VERSION 5.8 ;
BUSBITCHARS "[]" ;
DIVIDERCHAR "/" ;
UNITS
    DATABASE MICRONS 1000 ;
END UNITS

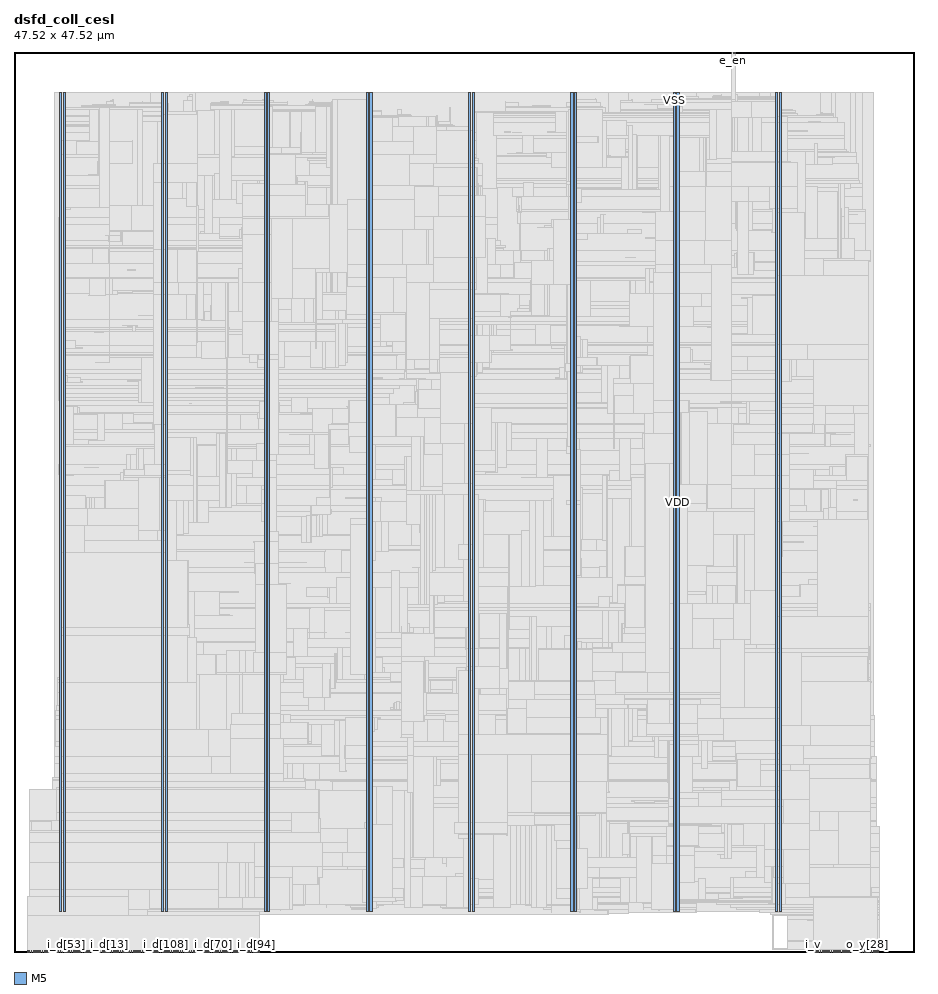
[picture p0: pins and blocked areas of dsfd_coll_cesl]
MACRO dsfd_coll_cesl
  FOREIGN dsfd_coll_cesl 0 0 ;
  CLASS BLOCK ;
  SIZE 47.52 BY 47.52 ;
  PIN ck
    DIRECTION INPUT ;
    USE SIGNAL ;
    PORT
      LAYER M5 ;
        RECT  37.872 47.436 37.896 47.52 ;
    END
  END ck
  PIN e_en
    DIRECTION INPUT ;
    USE SIGNAL ;
    PORT
      LAYER M5 ;
        RECT  37.968 47.436 37.992 47.52 ;
    END
  END e_en
  PIN i_d[0]
    DIRECTION INPUT ;
    USE SIGNAL ;
    PORT
      LAYER M5 ;
        RECT  3.792 0 3.816 0.084 ;
    END
  END i_d[0]
  PIN i_d[100]
    DIRECTION INPUT ;
    USE SIGNAL ;
    PORT
      LAYER M5 ;
        RECT  7.248 0 7.272 0.084 ;
    END
  END i_d[100]
  PIN i_d[101]
    DIRECTION INPUT ;
    USE SIGNAL ;
    PORT
      LAYER M5 ;
        RECT  7.344 0 7.368 0.084 ;
    END
  END i_d[101]
  PIN i_d[102]
    DIRECTION INPUT ;
    USE SIGNAL ;
    PORT
      LAYER M5 ;
        RECT  7.44 0 7.464 0.084 ;
    END
  END i_d[102]
  PIN i_d[103]
    DIRECTION INPUT ;
    USE SIGNAL ;
    PORT
      LAYER M5 ;
        RECT  7.536 0 7.56 0.084 ;
    END
  END i_d[103]
  PIN i_d[104]
    DIRECTION INPUT ;
    USE SIGNAL ;
    PORT
      LAYER M5 ;
        RECT  7.632 0 7.656 0.084 ;
    END
  END i_d[104]
  PIN i_d[105]
    DIRECTION INPUT ;
    USE SIGNAL ;
    PORT
      LAYER M5 ;
        RECT  7.728 0 7.752 0.084 ;
    END
  END i_d[105]
  PIN i_d[106]
    DIRECTION INPUT ;
    USE SIGNAL ;
    PORT
      LAYER M5 ;
        RECT  7.824 0 7.848 0.084 ;
    END
  END i_d[106]
  PIN i_d[107]
    DIRECTION INPUT ;
    USE SIGNAL ;
    PORT
      LAYER M5 ;
        RECT  7.92 0 7.944 0.084 ;
    END
  END i_d[107]
  PIN i_d[108]
    DIRECTION INPUT ;
    USE SIGNAL ;
    PORT
      LAYER M5 ;
        RECT  8.016 0 8.04 0.084 ;
    END
  END i_d[108]
  PIN i_d[109]
    DIRECTION INPUT ;
    USE SIGNAL ;
    PORT
      LAYER M5 ;
        RECT  8.112 0 8.136 0.084 ;
    END
  END i_d[109]
  PIN i_d[10]
    DIRECTION INPUT ;
    USE SIGNAL ;
    PORT
      LAYER M5 ;
        RECT  4.752 0 4.776 0.084 ;
    END
  END i_d[10]
  PIN i_d[110]
    DIRECTION INPUT ;
    USE SIGNAL ;
    PORT
      LAYER M5 ;
        RECT  8.208 0 8.232 0.084 ;
    END
  END i_d[110]
  PIN i_d[111]
    DIRECTION INPUT ;
    USE SIGNAL ;
    PORT
      LAYER M5 ;
        RECT  8.304 0 8.328 0.084 ;
    END
  END i_d[111]
  PIN i_d[112]
    DIRECTION INPUT ;
    USE SIGNAL ;
    PORT
      LAYER M5 ;
        RECT  8.4 0 8.424 0.084 ;
    END
  END i_d[112]
  PIN i_d[113]
    DIRECTION INPUT ;
    USE SIGNAL ;
    PORT
      LAYER M5 ;
        RECT  8.496 0 8.52 0.084 ;
    END
  END i_d[113]
  PIN i_d[114]
    DIRECTION INPUT ;
    USE SIGNAL ;
    PORT
      LAYER M5 ;
        RECT  8.592 0 8.616 0.084 ;
    END
  END i_d[114]
  PIN i_d[115]
    DIRECTION INPUT ;
    USE SIGNAL ;
    PORT
      LAYER M5 ;
        RECT  8.688 0 8.712 0.084 ;
    END
  END i_d[115]
  PIN i_d[116]
    DIRECTION INPUT ;
    USE SIGNAL ;
    PORT
      LAYER M5 ;
        RECT  8.784 0 8.808 0.084 ;
    END
  END i_d[116]
  PIN i_d[117]
    DIRECTION INPUT ;
    USE SIGNAL ;
    PORT
      LAYER M5 ;
        RECT  8.88 0 8.904 0.084 ;
    END
  END i_d[117]
  PIN i_d[118]
    DIRECTION INPUT ;
    USE SIGNAL ;
    PORT
      LAYER M5 ;
        RECT  8.976 0 9 0.084 ;
    END
  END i_d[118]
  PIN i_d[119]
    DIRECTION INPUT ;
    USE SIGNAL ;
    PORT
      LAYER M5 ;
        RECT  9.072 0 9.096 0.084 ;
    END
  END i_d[119]
  PIN i_d[11]
    DIRECTION INPUT ;
    USE SIGNAL ;
    PORT
      LAYER M5 ;
        RECT  4.848 0 4.872 0.084 ;
    END
  END i_d[11]
  PIN i_d[120]
    DIRECTION INPUT ;
    USE SIGNAL ;
    PORT
      LAYER M5 ;
        RECT  9.168 0 9.192 0.084 ;
    END
  END i_d[120]
  PIN i_d[121]
    DIRECTION INPUT ;
    USE SIGNAL ;
    PORT
      LAYER M5 ;
        RECT  9.264 0 9.288 0.084 ;
    END
  END i_d[121]
  PIN i_d[122]
    DIRECTION INPUT ;
    USE SIGNAL ;
    PORT
      LAYER M5 ;
        RECT  9.36 0 9.384 0.084 ;
    END
  END i_d[122]
  PIN i_d[123]
    DIRECTION INPUT ;
    USE SIGNAL ;
    PORT
      LAYER M5 ;
        RECT  9.456 0 9.48 0.084 ;
    END
  END i_d[123]
  PIN i_d[124]
    DIRECTION INPUT ;
    USE SIGNAL ;
    PORT
      LAYER M5 ;
        RECT  9.552 0 9.576 0.084 ;
    END
  END i_d[124]
  PIN i_d[125]
    DIRECTION INPUT ;
    USE SIGNAL ;
    PORT
      LAYER M5 ;
        RECT  9.648 0 9.672 0.084 ;
    END
  END i_d[125]
  PIN i_d[126]
    DIRECTION INPUT ;
    USE SIGNAL ;
    PORT
      LAYER M5 ;
        RECT  9.744 0 9.768 0.084 ;
    END
  END i_d[126]
  PIN i_d[127]
    DIRECTION INPUT ;
    USE SIGNAL ;
    PORT
      LAYER M5 ;
        RECT  9.84 0 9.864 0.084 ;
    END
  END i_d[127]
  PIN i_d[12]
    DIRECTION INPUT ;
    USE SIGNAL ;
    PORT
      LAYER M5 ;
        RECT  4.944 0 4.968 0.084 ;
    END
  END i_d[12]
  PIN i_d[13]
    DIRECTION INPUT ;
    USE SIGNAL ;
    PORT
      LAYER M5 ;
        RECT  5.04 0 5.064 0.084 ;
    END
  END i_d[13]
  PIN i_d[14]
    DIRECTION INPUT ;
    USE SIGNAL ;
    PORT
      LAYER M5 ;
        RECT  5.136 0 5.16 0.084 ;
    END
  END i_d[14]
  PIN i_d[15]
    DIRECTION INPUT ;
    USE SIGNAL ;
    PORT
      LAYER M5 ;
        RECT  5.232 0 5.256 0.084 ;
    END
  END i_d[15]
  PIN i_d[16]
    DIRECTION INPUT ;
    USE SIGNAL ;
    PORT
      LAYER M5 ;
        RECT  5.328 0 5.352 0.084 ;
    END
  END i_d[16]
  PIN i_d[17]
    DIRECTION INPUT ;
    USE SIGNAL ;
    PORT
      LAYER M5 ;
        RECT  5.424 0 5.448 0.084 ;
    END
  END i_d[17]
  PIN i_d[18]
    DIRECTION INPUT ;
    USE SIGNAL ;
    PORT
      LAYER M5 ;
        RECT  5.52 0 5.544 0.084 ;
    END
  END i_d[18]
  PIN i_d[19]
    DIRECTION INPUT ;
    USE SIGNAL ;
    PORT
      LAYER M5 ;
        RECT  5.616 0 5.64 0.084 ;
    END
  END i_d[19]
  PIN i_d[1]
    DIRECTION INPUT ;
    USE SIGNAL ;
    PORT
      LAYER M5 ;
        RECT  3.888 0 3.912 0.084 ;
    END
  END i_d[1]
  PIN i_d[20]
    DIRECTION INPUT ;
    USE SIGNAL ;
    PORT
      LAYER M5 ;
        RECT  5.712 0 5.736 0.084 ;
    END
  END i_d[20]
  PIN i_d[21]
    DIRECTION INPUT ;
    USE SIGNAL ;
    PORT
      LAYER M5 ;
        RECT  5.808 0 5.832 0.084 ;
    END
  END i_d[21]
  PIN i_d[22]
    DIRECTION INPUT ;
    USE SIGNAL ;
    PORT
      LAYER M5 ;
        RECT  5.904 0 5.928 0.084 ;
    END
  END i_d[22]
  PIN i_d[23]
    DIRECTION INPUT ;
    USE SIGNAL ;
    PORT
      LAYER M5 ;
        RECT  6 0 6.024 0.084 ;
    END
  END i_d[23]
  PIN i_d[24]
    DIRECTION INPUT ;
    USE SIGNAL ;
    PORT
      LAYER M5 ;
        RECT  6.096 0 6.12 0.084 ;
    END
  END i_d[24]
  PIN i_d[25]
    DIRECTION INPUT ;
    USE SIGNAL ;
    PORT
      LAYER M5 ;
        RECT  6.192 0 6.216 0.084 ;
    END
  END i_d[25]
  PIN i_d[26]
    DIRECTION INPUT ;
    USE SIGNAL ;
    PORT
      LAYER M5 ;
        RECT  6.288 0 6.312 0.084 ;
    END
  END i_d[26]
  PIN i_d[27]
    DIRECTION INPUT ;
    USE SIGNAL ;
    PORT
      LAYER M5 ;
        RECT  6.384 0 6.408 0.084 ;
    END
  END i_d[27]
  PIN i_d[28]
    DIRECTION INPUT ;
    USE SIGNAL ;
    PORT
      LAYER M5 ;
        RECT  6.48 0 6.504 0.084 ;
    END
  END i_d[28]
  PIN i_d[29]
    DIRECTION INPUT ;
    USE SIGNAL ;
    PORT
      LAYER M5 ;
        RECT  6.576 0 6.6 0.084 ;
    END
  END i_d[29]
  PIN i_d[2]
    DIRECTION INPUT ;
    USE SIGNAL ;
    PORT
      LAYER M5 ;
        RECT  3.984 0 4.008 0.084 ;
    END
  END i_d[2]
  PIN i_d[30]
    DIRECTION INPUT ;
    USE SIGNAL ;
    PORT
      LAYER M5 ;
        RECT  6.672 0 6.696 0.084 ;
    END
  END i_d[30]
  PIN i_d[31]
    DIRECTION INPUT ;
    USE SIGNAL ;
    PORT
      LAYER M5 ;
        RECT  6.768 0 6.792 0.084 ;
    END
  END i_d[31]
  PIN i_d[32]
    DIRECTION INPUT ;
    USE SIGNAL ;
    PORT
      LAYER M5 ;
        RECT  0.72 0 0.744 0.084 ;
    END
  END i_d[32]
  PIN i_d[33]
    DIRECTION INPUT ;
    USE SIGNAL ;
    PORT
      LAYER M5 ;
        RECT  0.816 0 0.84 0.084 ;
    END
  END i_d[33]
  PIN i_d[34]
    DIRECTION INPUT ;
    USE SIGNAL ;
    PORT
      LAYER M5 ;
        RECT  0.912 0 0.936 0.084 ;
    END
  END i_d[34]
  PIN i_d[35]
    DIRECTION INPUT ;
    USE SIGNAL ;
    PORT
      LAYER M5 ;
        RECT  1.008 0 1.032 0.084 ;
    END
  END i_d[35]
  PIN i_d[36]
    DIRECTION INPUT ;
    USE SIGNAL ;
    PORT
      LAYER M5 ;
        RECT  1.104 0 1.128 0.084 ;
    END
  END i_d[36]
  PIN i_d[37]
    DIRECTION INPUT ;
    USE SIGNAL ;
    PORT
      LAYER M5 ;
        RECT  1.2 0 1.224 0.084 ;
    END
  END i_d[37]
  PIN i_d[38]
    DIRECTION INPUT ;
    USE SIGNAL ;
    PORT
      LAYER M5 ;
        RECT  1.296 0 1.32 0.084 ;
    END
  END i_d[38]
  PIN i_d[39]
    DIRECTION INPUT ;
    USE SIGNAL ;
    PORT
      LAYER M5 ;
        RECT  1.392 0 1.416 0.084 ;
    END
  END i_d[39]
  PIN i_d[3]
    DIRECTION INPUT ;
    USE SIGNAL ;
    PORT
      LAYER M5 ;
        RECT  4.08 0 4.104 0.084 ;
    END
  END i_d[3]
  PIN i_d[40]
    DIRECTION INPUT ;
    USE SIGNAL ;
    PORT
      LAYER M5 ;
        RECT  1.488 0 1.512 0.084 ;
    END
  END i_d[40]
  PIN i_d[41]
    DIRECTION INPUT ;
    USE SIGNAL ;
    PORT
      LAYER M5 ;
        RECT  1.584 0 1.608 0.084 ;
    END
  END i_d[41]
  PIN i_d[42]
    DIRECTION INPUT ;
    USE SIGNAL ;
    PORT
      LAYER M5 ;
        RECT  1.68 0 1.704 0.084 ;
    END
  END i_d[42]
  PIN i_d[43]
    DIRECTION INPUT ;
    USE SIGNAL ;
    PORT
      LAYER M5 ;
        RECT  1.776 0 1.8 0.084 ;
    END
  END i_d[43]
  PIN i_d[44]
    DIRECTION INPUT ;
    USE SIGNAL ;
    PORT
      LAYER M5 ;
        RECT  1.872 0 1.896 0.084 ;
    END
  END i_d[44]
  PIN i_d[45]
    DIRECTION INPUT ;
    USE SIGNAL ;
    PORT
      LAYER M5 ;
        RECT  1.968 0 1.992 0.084 ;
    END
  END i_d[45]
  PIN i_d[46]
    DIRECTION INPUT ;
    USE SIGNAL ;
    PORT
      LAYER M5 ;
        RECT  2.064 0 2.088 0.084 ;
    END
  END i_d[46]
  PIN i_d[47]
    DIRECTION INPUT ;
    USE SIGNAL ;
    PORT
      LAYER M5 ;
        RECT  2.16 0 2.184 0.084 ;
    END
  END i_d[47]
  PIN i_d[48]
    DIRECTION INPUT ;
    USE SIGNAL ;
    PORT
      LAYER M5 ;
        RECT  2.256 0 2.28 0.084 ;
    END
  END i_d[48]
  PIN i_d[49]
    DIRECTION INPUT ;
    USE SIGNAL ;
    PORT
      LAYER M5 ;
        RECT  2.352 0 2.376 0.084 ;
    END
  END i_d[49]
  PIN i_d[4]
    DIRECTION INPUT ;
    USE SIGNAL ;
    PORT
      LAYER M5 ;
        RECT  4.176 0 4.2 0.084 ;
    END
  END i_d[4]
  PIN i_d[50]
    DIRECTION INPUT ;
    USE SIGNAL ;
    PORT
      LAYER M5 ;
        RECT  2.448 0 2.472 0.084 ;
    END
  END i_d[50]
  PIN i_d[51]
    DIRECTION INPUT ;
    USE SIGNAL ;
    PORT
      LAYER M5 ;
        RECT  2.544 0 2.568 0.084 ;
    END
  END i_d[51]
  PIN i_d[52]
    DIRECTION INPUT ;
    USE SIGNAL ;
    PORT
      LAYER M5 ;
        RECT  2.64 0 2.664 0.084 ;
    END
  END i_d[52]
  PIN i_d[53]
    DIRECTION INPUT ;
    USE SIGNAL ;
    PORT
      LAYER M5 ;
        RECT  2.736 0 2.76 0.084 ;
    END
  END i_d[53]
  PIN i_d[54]
    DIRECTION INPUT ;
    USE SIGNAL ;
    PORT
      LAYER M5 ;
        RECT  2.832 0 2.856 0.084 ;
    END
  END i_d[54]
  PIN i_d[55]
    DIRECTION INPUT ;
    USE SIGNAL ;
    PORT
      LAYER M5 ;
        RECT  2.928 0 2.952 0.084 ;
    END
  END i_d[55]
  PIN i_d[56]
    DIRECTION INPUT ;
    USE SIGNAL ;
    PORT
      LAYER M5 ;
        RECT  3.024 0 3.048 0.084 ;
    END
  END i_d[56]
  PIN i_d[57]
    DIRECTION INPUT ;
    USE SIGNAL ;
    PORT
      LAYER M5 ;
        RECT  3.12 0 3.144 0.084 ;
    END
  END i_d[57]
  PIN i_d[58]
    DIRECTION INPUT ;
    USE SIGNAL ;
    PORT
      LAYER M5 ;
        RECT  3.216 0 3.24 0.084 ;
    END
  END i_d[58]
  PIN i_d[59]
    DIRECTION INPUT ;
    USE SIGNAL ;
    PORT
      LAYER M5 ;
        RECT  3.312 0 3.336 0.084 ;
    END
  END i_d[59]
  PIN i_d[5]
    DIRECTION INPUT ;
    USE SIGNAL ;
    PORT
      LAYER M5 ;
        RECT  4.272 0 4.296 0.084 ;
    END
  END i_d[5]
  PIN i_d[60]
    DIRECTION INPUT ;
    USE SIGNAL ;
    PORT
      LAYER M5 ;
        RECT  3.408 0 3.432 0.084 ;
    END
  END i_d[60]
  PIN i_d[61]
    DIRECTION INPUT ;
    USE SIGNAL ;
    PORT
      LAYER M5 ;
        RECT  3.504 0 3.528 0.084 ;
    END
  END i_d[61]
  PIN i_d[62]
    DIRECTION INPUT ;
    USE SIGNAL ;
    PORT
      LAYER M5 ;
        RECT  3.6 0 3.624 0.084 ;
    END
  END i_d[62]
  PIN i_d[63]
    DIRECTION INPUT ;
    USE SIGNAL ;
    PORT
      LAYER M5 ;
        RECT  3.696 0 3.72 0.084 ;
    END
  END i_d[63]
  PIN i_d[64]
    DIRECTION INPUT ;
    USE SIGNAL ;
    PORT
      LAYER M5 ;
        RECT  9.936 0 9.96 0.084 ;
    END
  END i_d[64]
  PIN i_d[65]
    DIRECTION INPUT ;
    USE SIGNAL ;
    PORT
      LAYER M5 ;
        RECT  10.032 0 10.056 0.084 ;
    END
  END i_d[65]
  PIN i_d[66]
    DIRECTION INPUT ;
    USE SIGNAL ;
    PORT
      LAYER M5 ;
        RECT  10.128 0 10.152 0.084 ;
    END
  END i_d[66]
  PIN i_d[67]
    DIRECTION INPUT ;
    USE SIGNAL ;
    PORT
      LAYER M5 ;
        RECT  10.224 0 10.248 0.084 ;
    END
  END i_d[67]
  PIN i_d[68]
    DIRECTION INPUT ;
    USE SIGNAL ;
    PORT
      LAYER M5 ;
        RECT  10.32 0 10.344 0.084 ;
    END
  END i_d[68]
  PIN i_d[69]
    DIRECTION INPUT ;
    USE SIGNAL ;
    PORT
      LAYER M5 ;
        RECT  10.416 0 10.44 0.084 ;
    END
  END i_d[69]
  PIN i_d[6]
    DIRECTION INPUT ;
    USE SIGNAL ;
    PORT
      LAYER M5 ;
        RECT  4.368 0 4.392 0.084 ;
    END
  END i_d[6]
  PIN i_d[70]
    DIRECTION INPUT ;
    USE SIGNAL ;
    PORT
      LAYER M5 ;
        RECT  10.512 0 10.536 0.084 ;
    END
  END i_d[70]
  PIN i_d[71]
    DIRECTION INPUT ;
    USE SIGNAL ;
    PORT
      LAYER M5 ;
        RECT  10.608 0 10.632 0.084 ;
    END
  END i_d[71]
  PIN i_d[72]
    DIRECTION INPUT ;
    USE SIGNAL ;
    PORT
      LAYER M5 ;
        RECT  10.704 0 10.728 0.084 ;
    END
  END i_d[72]
  PIN i_d[73]
    DIRECTION INPUT ;
    USE SIGNAL ;
    PORT
      LAYER M5 ;
        RECT  10.8 0 10.824 0.084 ;
    END
  END i_d[73]
  PIN i_d[74]
    DIRECTION INPUT ;
    USE SIGNAL ;
    PORT
      LAYER M5 ;
        RECT  10.896 0 10.92 0.084 ;
    END
  END i_d[74]
  PIN i_d[75]
    DIRECTION INPUT ;
    USE SIGNAL ;
    PORT
      LAYER M5 ;
        RECT  10.992 0 11.016 0.084 ;
    END
  END i_d[75]
  PIN i_d[76]
    DIRECTION INPUT ;
    USE SIGNAL ;
    PORT
      LAYER M5 ;
        RECT  11.088 0 11.112 0.084 ;
    END
  END i_d[76]
  PIN i_d[77]
    DIRECTION INPUT ;
    USE SIGNAL ;
    PORT
      LAYER M5 ;
        RECT  11.184 0 11.208 0.084 ;
    END
  END i_d[77]
  PIN i_d[78]
    DIRECTION INPUT ;
    USE SIGNAL ;
    PORT
      LAYER M5 ;
        RECT  11.28 0 11.304 0.084 ;
    END
  END i_d[78]
  PIN i_d[79]
    DIRECTION INPUT ;
    USE SIGNAL ;
    PORT
      LAYER M5 ;
        RECT  11.376 0 11.4 0.084 ;
    END
  END i_d[79]
  PIN i_d[7]
    DIRECTION INPUT ;
    USE SIGNAL ;
    PORT
      LAYER M5 ;
        RECT  4.464 0 4.488 0.084 ;
    END
  END i_d[7]
  PIN i_d[80]
    DIRECTION INPUT ;
    USE SIGNAL ;
    PORT
      LAYER M5 ;
        RECT  11.472 0 11.496 0.084 ;
    END
  END i_d[80]
  PIN i_d[81]
    DIRECTION INPUT ;
    USE SIGNAL ;
    PORT
      LAYER M5 ;
        RECT  11.568 0 11.592 0.084 ;
    END
  END i_d[81]
  PIN i_d[82]
    DIRECTION INPUT ;
    USE SIGNAL ;
    PORT
      LAYER M5 ;
        RECT  11.664 0 11.688 0.084 ;
    END
  END i_d[82]
  PIN i_d[83]
    DIRECTION INPUT ;
    USE SIGNAL ;
    PORT
      LAYER M5 ;
        RECT  11.76 0 11.784 0.084 ;
    END
  END i_d[83]
  PIN i_d[84]
    DIRECTION INPUT ;
    USE SIGNAL ;
    PORT
      LAYER M5 ;
        RECT  11.856 0 11.88 0.084 ;
    END
  END i_d[84]
  PIN i_d[85]
    DIRECTION INPUT ;
    USE SIGNAL ;
    PORT
      LAYER M5 ;
        RECT  11.952 0 11.976 0.084 ;
    END
  END i_d[85]
  PIN i_d[86]
    DIRECTION INPUT ;
    USE SIGNAL ;
    PORT
      LAYER M5 ;
        RECT  12.048 0 12.072 0.084 ;
    END
  END i_d[86]
  PIN i_d[87]
    DIRECTION INPUT ;
    USE SIGNAL ;
    PORT
      LAYER M5 ;
        RECT  12.144 0 12.168 0.084 ;
    END
  END i_d[87]
  PIN i_d[88]
    DIRECTION INPUT ;
    USE SIGNAL ;
    PORT
      LAYER M5 ;
        RECT  12.24 0 12.264 0.084 ;
    END
  END i_d[88]
  PIN i_d[89]
    DIRECTION INPUT ;
    USE SIGNAL ;
    PORT
      LAYER M5 ;
        RECT  12.336 0 12.36 0.084 ;
    END
  END i_d[89]
  PIN i_d[8]
    DIRECTION INPUT ;
    USE SIGNAL ;
    PORT
      LAYER M5 ;
        RECT  4.56 0 4.584 0.084 ;
    END
  END i_d[8]
  PIN i_d[90]
    DIRECTION INPUT ;
    USE SIGNAL ;
    PORT
      LAYER M5 ;
        RECT  12.432 0 12.456 0.084 ;
    END
  END i_d[90]
  PIN i_d[91]
    DIRECTION INPUT ;
    USE SIGNAL ;
    PORT
      LAYER M5 ;
        RECT  12.528 0 12.552 0.084 ;
    END
  END i_d[91]
  PIN i_d[92]
    DIRECTION INPUT ;
    USE SIGNAL ;
    PORT
      LAYER M5 ;
        RECT  12.624 0 12.648 0.084 ;
    END
  END i_d[92]
  PIN i_d[93]
    DIRECTION INPUT ;
    USE SIGNAL ;
    PORT
      LAYER M5 ;
        RECT  12.72 0 12.744 0.084 ;
    END
  END i_d[93]
  PIN i_d[94]
    DIRECTION INPUT ;
    USE SIGNAL ;
    PORT
      LAYER M5 ;
        RECT  12.816 0 12.84 0.084 ;
    END
  END i_d[94]
  PIN i_d[95]
    DIRECTION INPUT ;
    USE SIGNAL ;
    PORT
      LAYER M5 ;
        RECT  12.912 0 12.936 0.084 ;
    END
  END i_d[95]
  PIN i_d[96]
    DIRECTION INPUT ;
    USE SIGNAL ;
    PORT
      LAYER M5 ;
        RECT  6.864 0 6.888 0.084 ;
    END
  END i_d[96]
  PIN i_d[97]
    DIRECTION INPUT ;
    USE SIGNAL ;
    PORT
      LAYER M5 ;
        RECT  6.96 0 6.984 0.084 ;
    END
  END i_d[97]
  PIN i_d[98]
    DIRECTION INPUT ;
    USE SIGNAL ;
    PORT
      LAYER M5 ;
        RECT  7.056 0 7.08 0.084 ;
    END
  END i_d[98]
  PIN i_d[99]
    DIRECTION INPUT ;
    USE SIGNAL ;
    PORT
      LAYER M5 ;
        RECT  7.152 0 7.176 0.084 ;
    END
  END i_d[99]
  PIN i_d[9]
    DIRECTION INPUT ;
    USE SIGNAL ;
    PORT
      LAYER M5 ;
        RECT  4.656 0 4.68 0.084 ;
    END
  END i_d[9]
  PIN i_v
    DIRECTION INPUT ;
    USE SIGNAL ;
    PORT
      LAYER M5 ;
        RECT  42.192 0 42.216 0.084 ;
    END
  END i_v
  PIN o_pe
    DIRECTION OUTPUT ;
    USE SIGNAL ;
    PORT
      LAYER M5 ;
        RECT  42.288 0 42.312 0.084 ;
    END
  END o_pe
  PIN o_y[0]
    DIRECTION OUTPUT ;
    USE SIGNAL ;
    PORT
      LAYER M5 ;
        RECT  42.384 0 42.408 0.084 ;
    END
  END o_y[0]
  PIN o_y[10]
    DIRECTION OUTPUT ;
    USE SIGNAL ;
    PORT
      LAYER M5 ;
        RECT  43.344 0 43.368 0.084 ;
    END
  END o_y[10]
  PIN o_y[11]
    DIRECTION OUTPUT ;
    USE SIGNAL ;
    PORT
      LAYER M5 ;
        RECT  43.44 0 43.464 0.084 ;
    END
  END o_y[11]
  PIN o_y[12]
    DIRECTION OUTPUT ;
    USE SIGNAL ;
    PORT
      LAYER M5 ;
        RECT  43.536 0 43.56 0.084 ;
    END
  END o_y[12]
  PIN o_y[13]
    DIRECTION OUTPUT ;
    USE SIGNAL ;
    PORT
      LAYER M5 ;
        RECT  43.632 0 43.656 0.084 ;
    END
  END o_y[13]
  PIN o_y[14]
    DIRECTION OUTPUT ;
    USE SIGNAL ;
    PORT
      LAYER M5 ;
        RECT  43.728 0 43.752 0.084 ;
    END
  END o_y[14]
  PIN o_y[15]
    DIRECTION OUTPUT ;
    USE SIGNAL ;
    PORT
      LAYER M5 ;
        RECT  43.824 0 43.848 0.084 ;
    END
  END o_y[15]
  PIN o_y[16]
    DIRECTION OUTPUT ;
    USE SIGNAL ;
    PORT
      LAYER M5 ;
        RECT  43.92 0 43.944 0.084 ;
    END
  END o_y[16]
  PIN o_y[17]
    DIRECTION OUTPUT ;
    USE SIGNAL ;
    PORT
      LAYER M5 ;
        RECT  44.016 0 44.04 0.084 ;
    END
  END o_y[17]
  PIN o_y[18]
    DIRECTION OUTPUT ;
    USE SIGNAL ;
    PORT
      LAYER M5 ;
        RECT  44.112 0 44.136 0.084 ;
    END
  END o_y[18]
  PIN o_y[19]
    DIRECTION OUTPUT ;
    USE SIGNAL ;
    PORT
      LAYER M5 ;
        RECT  44.208 0 44.232 0.084 ;
    END
  END o_y[19]
  PIN o_y[1]
    DIRECTION OUTPUT ;
    USE SIGNAL ;
    PORT
      LAYER M5 ;
        RECT  42.48 0 42.504 0.084 ;
    END
  END o_y[1]
  PIN o_y[20]
    DIRECTION OUTPUT ;
    USE SIGNAL ;
    PORT
      LAYER M5 ;
        RECT  44.304 0 44.328 0.084 ;
    END
  END o_y[20]
  PIN o_y[21]
    DIRECTION OUTPUT ;
    USE SIGNAL ;
    PORT
      LAYER M5 ;
        RECT  44.4 0 44.424 0.084 ;
    END
  END o_y[21]
  PIN o_y[22]
    DIRECTION OUTPUT ;
    USE SIGNAL ;
    PORT
      LAYER M5 ;
        RECT  44.496 0 44.52 0.084 ;
    END
  END o_y[22]
  PIN o_y[23]
    DIRECTION OUTPUT ;
    USE SIGNAL ;
    PORT
      LAYER M5 ;
        RECT  44.592 0 44.616 0.084 ;
    END
  END o_y[23]
  PIN o_y[24]
    DIRECTION OUTPUT ;
    USE SIGNAL ;
    PORT
      LAYER M5 ;
        RECT  44.688 0 44.712 0.084 ;
    END
  END o_y[24]
  PIN o_y[25]
    DIRECTION OUTPUT ;
    USE SIGNAL ;
    PORT
      LAYER M5 ;
        RECT  44.784 0 44.808 0.084 ;
    END
  END o_y[25]
  PIN o_y[26]
    DIRECTION OUTPUT ;
    USE SIGNAL ;
    PORT
      LAYER M5 ;
        RECT  44.88 0 44.904 0.084 ;
    END
  END o_y[26]
  PIN o_y[27]
    DIRECTION OUTPUT ;
    USE SIGNAL ;
    PORT
      LAYER M5 ;
        RECT  44.976 0 45 0.084 ;
    END
  END o_y[27]
  PIN o_y[28]
    DIRECTION OUTPUT ;
    USE SIGNAL ;
    PORT
      LAYER M5 ;
        RECT  45.072 0 45.096 0.084 ;
    END
  END o_y[28]
  PIN o_y[29]
    DIRECTION OUTPUT ;
    USE SIGNAL ;
    PORT
      LAYER M5 ;
        RECT  45.168 0 45.192 0.084 ;
    END
  END o_y[29]
  PIN o_y[2]
    DIRECTION OUTPUT ;
    USE SIGNAL ;
    PORT
      LAYER M5 ;
        RECT  42.576 0 42.6 0.084 ;
    END
  END o_y[2]
  PIN o_y[30]
    DIRECTION OUTPUT ;
    USE SIGNAL ;
    PORT
      LAYER M5 ;
        RECT  45.264 0 45.288 0.084 ;
    END
  END o_y[30]
  PIN o_y[31]
    DIRECTION OUTPUT ;
    USE SIGNAL ;
    PORT
      LAYER M5 ;
        RECT  45.36 0 45.384 0.084 ;
    END
  END o_y[31]
  PIN o_y[3]
    DIRECTION OUTPUT ;
    USE SIGNAL ;
    PORT
      LAYER M5 ;
        RECT  42.672 0 42.696 0.084 ;
    END
  END o_y[3]
  PIN o_y[4]
    DIRECTION OUTPUT ;
    USE SIGNAL ;
    PORT
      LAYER M5 ;
        RECT  42.768 0 42.792 0.084 ;
    END
  END o_y[4]
  PIN o_y[5]
    DIRECTION OUTPUT ;
    USE SIGNAL ;
    PORT
      LAYER M5 ;
        RECT  42.864 0 42.888 0.084 ;
    END
  END o_y[5]
  PIN o_y[6]
    DIRECTION OUTPUT ;
    USE SIGNAL ;
    PORT
      LAYER M5 ;
        RECT  42.96 0 42.984 0.084 ;
    END
  END o_y[6]
  PIN o_y[7]
    DIRECTION OUTPUT ;
    USE SIGNAL ;
    PORT
      LAYER M5 ;
        RECT  43.056 0 43.08 0.084 ;
    END
  END o_y[7]
  PIN o_y[8]
    DIRECTION OUTPUT ;
    USE SIGNAL ;
    PORT
      LAYER M5 ;
        RECT  43.152 0 43.176 0.084 ;
    END
  END o_y[8]
  PIN o_y[9]
    DIRECTION OUTPUT ;
    USE SIGNAL ;
    PORT
      LAYER M5 ;
        RECT  43.248 0 43.272 0.084 ;
    END
  END o_y[9]
  PIN o_ye[0]
    DIRECTION OUTPUT ;
    USE SIGNAL ;
    PORT
      LAYER M5 ;
        RECT  45.456 0 45.48 0.084 ;
    END
  END o_ye[0]
  PIN o_ye[1]
    DIRECTION OUTPUT ;
    USE SIGNAL ;
    PORT
      LAYER M5 ;
        RECT  45.552 0 45.576 0.084 ;
    END
  END o_ye[1]
  PIN o_yv
    DIRECTION OUTPUT ;
    USE SIGNAL ;
    PORT
      LAYER M5 ;
        RECT  45.648 0 45.672 0.084 ;
    END
  END o_yv
  PIN rs
    DIRECTION INPUT ;
    USE SIGNAL ;
    PORT
      LAYER M5 ;
        RECT  38.064 47.436 38.088 47.52 ;
    END
  END rs
  PIN VDD
    DIRECTION INOUT ;
    USE POWER ;
    PORT
      LAYER M5 ;
        RECT  40.392 2.151 40.512 45.369 ;
        RECT  34.992 2.151 35.112 45.369 ;
        RECT  29.592 2.151 29.712 45.369 ;
        RECT  24.192 2.151 24.312 45.369 ;
        RECT  18.792 2.151 18.912 45.369 ;
        RECT  13.392 2.151 13.512 45.369 ;
        RECT  7.992 2.151 8.112 45.369 ;
        RECT  2.592 2.151 2.712 45.369 ;
    END
  END VDD
  PIN VSS
    DIRECTION INOUT ;
    USE GROUND ;
    PORT
      LAYER M5 ;
        RECT  40.2 2.137 40.32 45.383 ;
        RECT  34.8 2.137 34.92 45.383 ;
        RECT  29.4 2.137 29.52 45.383 ;
        RECT  24 2.137 24.12 45.383 ;
        RECT  18.6 2.137 18.72 45.383 ;
        RECT  13.2 2.137 13.32 45.383 ;
        RECT  7.8 2.137 7.92 45.383 ;
        RECT  2.4 2.137 2.52 45.383 ;
    END
  END VSS
  # OT_OBS_CLOSED layer=M5 d_um=1.536 added=175
  OBS
    LAYER RVTN ;
     RECT  2.16 2.16 45.36 2.295 ;
     RECT  2.16 2.565 45.36 2.835 ;
     RECT  2.16 3.105 45.36 3.375 ;
     RECT  2.16 3.645 45.36 3.915 ;
     RECT  2.16 4.185 45.36 4.455 ;
     RECT  2.16 4.725 45.36 4.995 ;
     RECT  2.16 5.265 45.36 5.535 ;
     RECT  2.16 5.805 45.36 6.075 ;
     RECT  2.16 6.345 45.36 6.615 ;
     RECT  2.16 6.885 45.36 7.155 ;
     RECT  2.16 7.425 45.36 7.695 ;
     RECT  2.16 7.965 45.36 8.235 ;
     RECT  2.16 8.505 45.36 8.775 ;
     RECT  2.16 9.045 45.36 9.315 ;
     RECT  2.16 9.585 45.36 9.855 ;
     RECT  2.16 10.125 45.36 10.395 ;
     RECT  2.16 10.665 45.36 10.935 ;
     RECT  2.16 11.205 45.36 11.475 ;
     RECT  2.16 11.745 45.36 12.015 ;
     RECT  2.16 12.285 45.36 12.555 ;
     RECT  2.16 12.825 45.36 13.095 ;
     RECT  2.16 13.365 45.36 13.635 ;
     RECT  2.16 13.905 45.36 14.175 ;
     RECT  2.16 14.445 45.36 14.715 ;
     RECT  2.16 14.985 45.36 15.255 ;
     RECT  2.16 15.525 45.36 15.795 ;
     RECT  2.16 16.065 45.36 16.335 ;
     RECT  2.16 16.605 45.36 16.875 ;
     RECT  2.16 17.145 45.36 17.415 ;
     RECT  2.16 17.685 45.36 17.955 ;
     RECT  2.16 18.225 45.36 18.495 ;
     RECT  2.16 18.765 45.36 19.035 ;
     RECT  2.16 19.305 45.36 19.575 ;
     RECT  2.16 19.845 45.36 20.115 ;
     RECT  2.16 20.385 45.36 20.655 ;
     RECT  2.16 20.925 45.36 21.195 ;
     RECT  2.16 21.465 45.36 21.735 ;
     RECT  2.16 22.005 45.36 22.275 ;
     RECT  2.16 22.545 45.36 22.815 ;
     RECT  2.16 23.085 45.36 23.355 ;
     RECT  2.16 23.625 45.36 23.895 ;
     RECT  2.16 24.165 45.36 24.435 ;
     RECT  2.16 24.705 45.36 24.975 ;
     RECT  2.16 25.245 45.36 25.515 ;
     RECT  2.16 25.785 45.36 26.055 ;
     RECT  2.16 26.325 45.36 26.595 ;
     RECT  2.16 26.865 45.36 27.135 ;
     RECT  2.16 27.405 45.36 27.675 ;
     RECT  2.16 27.945 45.36 28.215 ;
     RECT  2.16 28.485 45.36 28.755 ;
     RECT  2.16 29.025 45.36 29.295 ;
     RECT  2.16 29.565 45.36 29.835 ;
     RECT  2.16 30.105 45.36 30.375 ;
     RECT  2.16 30.645 45.36 30.915 ;
     RECT  2.16 31.185 45.36 31.455 ;
     RECT  2.16 31.725 45.36 31.995 ;
     RECT  2.16 32.265 45.36 32.535 ;
     RECT  2.16 32.805 45.36 33.075 ;
     RECT  2.16 33.345 45.36 33.615 ;
     RECT  2.16 33.885 45.36 34.155 ;
     RECT  2.16 34.425 45.36 34.695 ;
     RECT  2.16 34.965 45.36 35.235 ;
     RECT  2.16 35.505 45.36 35.775 ;
     RECT  2.16 36.045 45.36 36.315 ;
     RECT  2.16 36.585 45.36 36.855 ;
     RECT  2.16 37.125 45.36 37.395 ;
     RECT  2.16 37.665 45.36 37.935 ;
     RECT  2.16 38.205 45.36 38.475 ;
     RECT  2.16 38.745 45.36 39.015 ;
     RECT  2.16 39.285 45.36 39.555 ;
     RECT  2.16 39.825 45.36 40.095 ;
     RECT  2.16 40.365 45.36 40.635 ;
     RECT  2.16 40.905 45.36 41.175 ;
     RECT  2.16 41.445 45.36 41.715 ;
     RECT  2.16 41.985 45.36 42.255 ;
     RECT  2.16 42.525 45.36 42.795 ;
     RECT  2.16 43.065 45.36 43.335 ;
     RECT  2.16 43.605 45.36 43.875 ;
     RECT  2.16 44.145 45.36 44.415 ;
     RECT  2.16 44.685 45.36 44.955 ;
     RECT  2.16 45.225 45.36 45.36 ;
    LAYER RVTP ;
     RECT  2.16 2.295 45.36 2.565 ;
     RECT  2.16 2.835 45.36 3.105 ;
     RECT  2.16 3.375 45.36 3.645 ;
     RECT  2.16 3.915 45.36 4.185 ;
     RECT  2.16 4.455 45.36 4.725 ;
     RECT  2.16 4.995 45.36 5.265 ;
     RECT  2.16 5.535 45.36 5.805 ;
     RECT  2.16 6.075 45.36 6.345 ;
     RECT  2.16 6.615 45.36 6.885 ;
     RECT  2.16 7.155 45.36 7.425 ;
     RECT  2.16 7.695 45.36 7.965 ;
     RECT  2.16 8.235 45.36 8.505 ;
     RECT  2.16 8.775 45.36 9.045 ;
     RECT  2.16 9.315 45.36 9.585 ;
     RECT  2.16 9.855 45.36 10.125 ;
     RECT  2.16 10.395 45.36 10.665 ;
     RECT  2.16 10.935 45.36 11.205 ;
     RECT  2.16 11.475 45.36 11.745 ;
     RECT  2.16 12.015 45.36 12.285 ;
     RECT  2.16 12.555 45.36 12.825 ;
     RECT  2.16 13.095 45.36 13.365 ;
     RECT  2.16 13.635 45.36 13.905 ;
     RECT  2.16 14.175 45.36 14.445 ;
     RECT  2.16 14.715 45.36 14.985 ;
     RECT  2.16 15.255 45.36 15.525 ;
     RECT  2.16 15.795 45.36 16.065 ;
     RECT  2.16 16.335 45.36 16.605 ;
     RECT  2.16 16.875 45.36 17.145 ;
     RECT  2.16 17.415 45.36 17.685 ;
     RECT  2.16 17.955 45.36 18.225 ;
     RECT  2.16 18.495 45.36 18.765 ;
     RECT  2.16 19.035 45.36 19.305 ;
     RECT  2.16 19.575 45.36 19.845 ;
     RECT  2.16 20.115 45.36 20.385 ;
     RECT  2.16 20.655 45.36 20.925 ;
     RECT  2.16 21.195 45.36 21.465 ;
     RECT  2.16 21.735 45.36 22.005 ;
     RECT  2.16 22.275 45.36 22.545 ;
     RECT  2.16 22.815 45.36 23.085 ;
     RECT  2.16 23.355 45.36 23.625 ;
     RECT  2.16 23.895 45.36 24.165 ;
     RECT  2.16 24.435 45.36 24.705 ;
     RECT  2.16 24.975 45.36 25.245 ;
     RECT  2.16 25.515 45.36 25.785 ;
     RECT  2.16 26.055 45.36 26.325 ;
     RECT  2.16 26.595 45.36 26.865 ;
     RECT  2.16 27.135 45.36 27.405 ;
     RECT  2.16 27.675 45.36 27.945 ;
     RECT  2.16 28.215 45.36 28.485 ;
     RECT  2.16 28.755 45.36 29.025 ;
     RECT  2.16 29.295 45.36 29.565 ;
     RECT  2.16 29.835 45.36 30.105 ;
     RECT  2.16 30.375 45.36 30.645 ;
     RECT  2.16 30.915 45.36 31.185 ;
     RECT  2.16 31.455 45.36 31.725 ;
     RECT  2.16 31.995 45.36 32.265 ;
     RECT  2.16 32.535 45.36 32.805 ;
     RECT  2.16 33.075 45.36 33.345 ;
     RECT  2.16 33.615 45.36 33.885 ;
     RECT  2.16 34.155 45.36 34.425 ;
     RECT  2.16 34.695 45.36 34.965 ;
     RECT  2.16 35.235 45.36 35.505 ;
     RECT  2.16 35.775 45.36 36.045 ;
     RECT  2.16 36.315 45.36 36.585 ;
     RECT  2.16 36.855 45.36 37.125 ;
     RECT  2.16 37.395 45.36 37.665 ;
     RECT  2.16 37.935 45.36 38.205 ;
     RECT  2.16 38.475 45.36 38.745 ;
     RECT  2.16 39.015 45.36 39.285 ;
     RECT  2.16 39.555 45.36 39.825 ;
     RECT  2.16 40.095 45.36 40.365 ;
     RECT  2.16 40.635 45.36 40.905 ;
     RECT  2.16 41.175 45.36 41.445 ;
     RECT  2.16 41.715 45.36 41.985 ;
     RECT  2.16 42.255 45.36 42.525 ;
     RECT  2.16 42.795 45.36 43.065 ;
     RECT  2.16 43.335 45.36 43.605 ;
     RECT  2.16 43.875 45.36 44.145 ;
     RECT  2.16 44.415 45.36 44.685 ;
     RECT  2.16 44.955 45.36 45.225 ;
    LAYER M1 ;
     RECT  2.16 2.151 45.36 45.369 ;
    LAYER M2 ;
     RECT  1.219 3.312 1.687 3.33 ;
     RECT  1.687 3.042 1.723 3.33 ;
     RECT  1.723 3.042 1.903 3.87 ;
     RECT  1.903 3.042 2.011 4.41 ;
     RECT  2.011 7.434 2.083 7.452 ;
     RECT  2.047 5.616 2.155 5.634 ;
     RECT  2.047 9.216 2.155 9.234 ;
     RECT  2.011 3.042 2.16 4.482 ;
     RECT  2.155 5.31 2.16 5.634 ;
     RECT  2.083 7.434 2.16 8.154 ;
     RECT  2.155 9.216 2.16 9.774 ;
     RECT  2.119 10.836 2.16 10.854 ;
     RECT  2.16 2.151 7.231 45.369 ;
     RECT  7.231 2.106 9.607 45.369 ;
     RECT  9.607 1.998 31.379 45.369 ;
     RECT  31.379 2.034 32.459 45.369 ;
     RECT  32.459 2.07 36.023 45.369 ;
     RECT  36.023 2.151 39.343 45.369 ;
     RECT  39.343 2.106 39.919 45.369 ;
     RECT  39.919 1.962 40.423 45.369 ;
     RECT  40.423 1.926 42.575 45.369 ;
     RECT  42.575 1.962 43.151 45.369 ;
     RECT  43.151 2.034 43.367 45.369 ;
     RECT  41.215 0.576 43.871 0.594 ;
     RECT  43.367 2.106 44.167 45.369 ;
     RECT  44.167 2.07 44.411 45.369 ;
     RECT  44.411 2.106 44.807 45.369 ;
     RECT  44.807 2.151 45.36 45.369 ;
     RECT  45.36 3.726 45.383 3.744 ;
     RECT  45.36 6.588 45.383 8.154 ;
     RECT  45.36 4.734 45.419 4.824 ;
     RECT  45.383 6.588 45.419 7.614 ;
     RECT  45.36 12.456 45.419 12.474 ;
     RECT  45.419 4.806 45.527 4.824 ;
     RECT  45.36 10.296 45.527 10.314 ;
     RECT  45.36 2.61 45.563 2.628 ;
     RECT  45.419 7.596 45.563 7.614 ;
     RECT  45.419 6.588 45.707 6.606 ;
    LAYER M3 ;
     RECT  42.264 0.091 43.866 0.187 ;
     RECT  5.508 0.091 5.886 0.221 ;
     RECT  5.508 0.221 5.526 0.317 ;
     RECT  11.016 0.091 11.034 0.475 ;
     RECT  41.544 0.187 43.866 0.475 ;
     RECT  44.712 0.091 45.702 0.475 ;
     RECT  11.016 0.475 11.25 0.523 ;
     RECT  41.544 0.475 45.702 0.523 ;
     RECT  2.772 0.091 3.438 0.571 ;
     RECT  40.86 0.523 45.702 0.599 ;
     RECT  12.456 0.091 12.474 0.667 ;
     RECT  8.676 0.091 8.694 1.099 ;
     RECT  8.64 1.099 8.694 1.147 ;
     RECT  10.908 0.523 11.25 1.627 ;
     RECT  12.456 0.667 12.582 1.627 ;
     RECT  8.64 1.147 9.162 1.675 ;
     RECT  2.772 0.571 4.014 1.723 ;
     RECT  7.38 1.099 7.398 1.723 ;
     RECT  8.64 1.675 9.774 1.723 ;
     RECT  10.908 1.627 12.582 1.723 ;
     RECT  40.86 0.599 43.434 1.723 ;
     RECT  44.208 0.599 45.702 1.723 ;
     RECT  2.196 1.723 12.87 1.771 ;
     RECT  40.068 0.139 40.086 1.921 ;
     RECT  40.86 1.723 45.702 1.921 ;
     RECT  40.068 1.921 45.702 1.957 ;
     RECT  39.924 1.957 45.702 2.101 ;
     RECT  2.196 1.771 12.942 2.143 ;
     RECT  29.88 2.101 29.898 2.143 ;
     RECT  31.356 1.993 31.374 2.191 ;
     RECT  30.672 2.191 31.374 2.227 ;
     RECT  32.436 2.029 32.454 2.227 ;
     RECT  39.348 2.101 45.702 2.227 ;
     RECT  14.076 2.191 14.094 2.251 ;
     RECT  34.056 2.191 34.074 2.251 ;
     RECT  34.815 2.143 34.905 2.251 ;
     RECT  17.82 2.227 17.838 2.263 ;
     RECT  18.615 2.143 18.705 2.263 ;
     RECT  28.368 2.065 28.386 2.263 ;
     RECT  34.056 2.251 34.905 2.263 ;
     RECT  36 2.065 36.018 2.263 ;
     RECT  39.276 2.227 45.702 2.263 ;
     RECT  17.82 2.263 18.705 2.293 ;
     RECT  17.82 2.293 18.882 2.299 ;
     RECT  24.015 2.143 24.105 2.299 ;
     RECT  17.82 2.299 19.134 2.335 ;
     RECT  22.608 2.299 24.105 2.335 ;
     RECT  27.972 2.263 28.386 2.335 ;
     RECT  20.7 2.335 20.718 2.347 ;
     RECT  25.776 2.335 25.866 2.347 ;
     RECT  17.784 2.335 19.134 2.371 ;
     RECT  22.608 2.335 24.354 2.371 ;
     RECT  33.228 2.227 33.246 2.371 ;
     RECT  34.056 2.263 36.018 2.371 ;
     RECT  38.16 2.263 45.702 2.371 ;
     RECT  2.196 2.143 13.305 2.413 ;
     RECT  14.076 2.251 14.67 2.413 ;
     RECT  2.196 2.413 14.67 2.461 ;
     RECT  17.784 2.371 19.242 2.461 ;
     RECT  20.628 2.347 20.718 2.461 ;
     RECT  21.456 2.335 21.546 2.461 ;
     RECT  22.536 2.371 24.354 2.461 ;
     RECT  27.324 2.335 28.386 2.461 ;
     RECT  29.415 2.143 29.898 2.461 ;
     RECT  16.488 2.371 16.506 2.497 ;
     RECT  17.496 2.461 19.494 2.497 ;
     RECT  27 2.461 29.898 2.497 ;
     RECT  30.672 2.227 32.454 2.497 ;
     RECT  37.836 2.371 45.702 2.497 ;
     RECT  2.196 2.461 15.354 2.533 ;
     RECT  25.776 2.347 26.226 2.569 ;
     RECT  27 2.497 32.454 2.569 ;
     RECT  33.228 2.371 36.018 2.587 ;
     RECT  16.488 2.497 19.494 2.605 ;
     RECT  20.628 2.461 24.498 2.605 ;
     RECT  33.192 2.587 36.018 2.605 ;
     RECT  37.08 2.497 45.702 2.605 ;
     RECT  16.488 2.605 24.498 2.641 ;
     RECT  25.236 2.569 32.454 2.641 ;
     RECT  33.192 2.605 45.702 2.641 ;
     RECT  2.196 2.533 15.75 2.731 ;
     RECT  16.488 2.641 45.702 2.731 ;
     RECT  2.196 2.731 45.702 2.875 ;
     RECT  1.728 2.875 45.702 2.923 ;
     RECT  1.224 2.923 45.702 3.137 ;
     RECT  1.224 3.137 29.697 3.335 ;
     RECT  30.528 3.137 45.702 3.389 ;
     RECT  1.728 3.335 22.59 3.713 ;
     RECT  1.728 3.713 22.23 3.839 ;
     RECT  1.728 3.839 21.654 3.875 ;
     RECT  23.328 3.335 29.697 3.883 ;
     RECT  23.328 3.883 29.754 3.931 ;
     RECT  23.328 3.931 30.006 4.145 ;
     RECT  23.76 4.145 30.006 4.289 ;
     RECT  1.908 3.875 21.654 4.415 ;
     RECT  23.796 4.289 30.006 4.459 ;
     RECT  30.888 3.389 45.702 4.459 ;
     RECT  22.824 4.531 22.842 4.657 ;
     RECT  2.016 4.415 21.654 4.891 ;
     RECT  2.016 4.891 21.726 5.161 ;
     RECT  22.608 4.657 22.842 5.161 ;
     RECT  2.016 5.161 22.842 5.305 ;
     RECT  23.796 4.459 45.702 5.305 ;
     RECT  2.016 5.305 45.702 5.495 ;
     RECT  2.016 5.495 22.41 6.277 ;
     RECT  23.292 5.495 45.702 6.277 ;
     RECT  2.016 6.277 45.702 6.611 ;
     RECT  2.016 6.611 45.558 6.881 ;
     RECT  18.54 6.881 45.558 6.941 ;
     RECT  2.016 6.881 17.694 7.457 ;
     RECT  18.615 6.941 45.558 7.619 ;
     RECT  18.615 7.619 45.522 7.861 ;
     RECT  2.052 7.457 17.694 7.897 ;
     RECT  2.052 7.897 17.802 7.997 ;
     RECT  16.812 7.997 17.802 8.167 ;
     RECT  18.576 7.861 45.522 8.167 ;
     RECT  16.812 8.167 45.522 9.013 ;
     RECT  2.052 7.997 15.93 9.049 ;
     RECT  16.704 9.013 45.522 9.049 ;
     RECT  2.052 9.049 45.522 9.113 ;
     RECT  2.052 9.113 15.282 9.239 ;
     RECT  2.124 9.239 15.282 9.931 ;
     RECT  16.128 9.113 45.522 9.931 ;
     RECT  2.124 9.931 45.522 10.319 ;
     RECT  2.124 10.319 45.414 10.859 ;
     RECT  2.196 10.859 45.414 11.129 ;
     RECT  2.196 11.129 21.834 12.253 ;
     RECT  22.68 11.129 45.414 12.253 ;
     RECT  2.196 12.253 45.414 12.479 ;
     RECT  2.196 12.479 45.234 12.749 ;
     RECT  2.232 12.749 15.534 13.019 ;
     RECT  16.38 12.749 45.054 13.639 ;
     RECT  16.38 13.639 45.198 13.675 ;
     RECT  2.304 13.019 15.534 13.711 ;
     RECT  16.308 13.675 45.198 13.711 ;
     RECT  2.304 13.711 45.198 14.251 ;
     RECT  2.304 14.251 45.234 14.369 ;
     RECT  2.304 14.369 45.198 14.513 ;
     RECT  2.415 14.513 45.198 15.215 ;
     RECT  2.415 15.215 9.198 15.287 ;
     RECT  10.008 15.215 45.198 15.581 ;
     RECT  15.516 15.581 45.198 16.061 ;
     RECT  2.415 15.287 9.054 16.141 ;
     RECT  2.415 16.141 9.234 16.339 ;
     RECT  10.008 15.581 14.742 16.339 ;
     RECT  2.415 16.339 14.742 16.411 ;
     RECT  15.516 16.061 31.05 16.565 ;
     RECT  2.415 16.411 14.778 17.077 ;
     RECT  15.516 16.565 15.606 17.077 ;
     RECT  16.416 16.565 31.05 18.031 ;
     RECT  31.932 16.061 45.198 18.031 ;
     RECT  2.415 17.077 15.606 18.121 ;
     RECT  2.415 18.121 15.678 18.193 ;
     RECT  16.416 18.031 45.198 18.193 ;
     RECT  2.415 18.193 45.198 18.419 ;
     RECT  2.415 18.419 45.054 20.039 ;
     RECT  17.28 20.039 45.054 20.059 ;
     RECT  2.415 20.039 16.434 20.309 ;
     RECT  2.415 20.309 16.398 21.127 ;
     RECT  17.28 20.059 45.126 21.191 ;
     RECT  2.415 21.127 16.434 21.271 ;
     RECT  17.28 21.191 29.97 21.271 ;
     RECT  2.415 21.271 29.97 21.973 ;
     RECT  30.744 21.191 45.126 21.973 ;
     RECT  2.415 21.973 45.126 23.279 ;
     RECT  2.415 23.279 41.85 23.585 ;
     RECT  13.068 23.585 41.742 24.403 ;
     RECT  42.66 23.279 45.126 24.403 ;
     RECT  2.415 23.585 12.294 24.637 ;
     RECT  13.068 24.403 45.126 24.637 ;
     RECT  2.415 24.637 45.126 25.213 ;
     RECT  2.376 25.213 45.126 25.745 ;
     RECT  2.415 25.745 45.126 26.671 ;
     RECT  2.415 26.671 45.234 26.789 ;
     RECT  2.415 26.789 45.126 27.437 ;
     RECT  2.415 27.437 15.786 27.599 ;
     RECT  16.596 27.437 45.126 27.869 ;
     RECT  16.776 27.869 37.314 27.905 ;
     RECT  16.812 27.905 37.314 27.917 ;
     RECT  2.415 27.599 11.97 28.381 ;
     RECT  12.888 27.599 15.786 28.381 ;
     RECT  38.232 27.869 45.126 28.409 ;
     RECT  2.415 28.381 15.786 28.493 ;
     RECT  16.812 27.917 37.134 28.679 ;
     RECT  15.48 28.493 15.786 28.687 ;
     RECT  16.812 28.679 21.222 28.687 ;
     RECT  15.48 28.687 21.222 28.715 ;
     RECT  21.96 28.679 37.134 28.759 ;
     RECT  38.232 28.409 45.054 28.759 ;
     RECT  2.415 28.493 14.67 28.831 ;
     RECT  21.96 28.759 45.054 28.985 ;
     RECT  20.592 28.715 21.222 29.021 ;
     RECT  2.412 28.831 14.67 29.101 ;
     RECT  2.34 29.101 14.67 29.263 ;
     RECT  15.48 28.715 19.818 29.263 ;
     RECT  22.032 28.985 45.054 29.489 ;
     RECT  2.34 29.263 19.818 29.497 ;
     RECT  21.132 29.021 21.222 29.605 ;
     RECT  2.34 29.497 20.034 29.767 ;
     RECT  2.34 29.767 20.358 29.911 ;
     RECT  21.132 29.605 21.294 29.911 ;
     RECT  2.34 29.911 21.294 30.235 ;
     RECT  22.068 29.489 45.054 30.235 ;
     RECT  2.34 30.235 45.054 30.569 ;
     RECT  2.34 30.569 44.946 30.749 ;
     RECT  21.132 30.749 44.946 30.797 ;
     RECT  34.488 30.797 44.946 31.253 ;
     RECT  2.34 30.749 20.178 31.495 ;
     RECT  2.34 31.495 20.25 31.531 ;
     RECT  21.132 30.797 33.426 31.531 ;
     RECT  2.34 31.531 33.426 31.649 ;
     RECT  2.34 31.649 19.998 31.997 ;
     RECT  20.736 31.649 33.426 31.999 ;
     RECT  34.632 31.253 44.946 31.999 ;
     RECT  20.736 31.999 44.946 32.063 ;
     RECT  20.736 32.063 27.522 32.099 ;
     RECT  28.332 32.063 44.946 32.189 ;
     RECT  2.34 31.997 19.962 32.737 ;
     RECT  20.736 32.099 21.258 32.737 ;
     RECT  2.34 32.737 21.258 32.845 ;
     RECT  21.996 32.099 27.522 32.845 ;
     RECT  2.34 32.845 27.522 32.873 ;
     RECT  12.168 32.873 27.522 32.881 ;
     RECT  2.34 32.873 11.358 32.999 ;
     RECT  34.272 32.189 44.946 33.007 ;
     RECT  28.332 32.189 33.426 33.079 ;
     RECT  12.168 32.881 27.558 33.151 ;
     RECT  28.332 33.079 33.462 33.151 ;
     RECT  34.2 33.007 44.946 33.151 ;
     RECT  12.168 33.151 44.946 33.305 ;
     RECT  2.34 32.999 11.322 33.413 ;
     RECT  12.168 33.305 33.534 33.539 ;
     RECT  10.008 33.413 11.322 33.835 ;
     RECT  12.168 33.539 25.686 33.835 ;
     RECT  26.604 33.539 33.534 33.953 ;
     RECT  26.676 33.953 33.534 34.123 ;
     RECT  34.272 33.305 44.946 34.123 ;
     RECT  10.008 33.835 25.686 34.735 ;
     RECT  26.676 34.123 44.946 34.735 ;
     RECT  2.34 33.413 9.09 34.781 ;
     RECT  10.008 34.735 44.946 35.371 ;
     RECT  2.34 34.781 8.838 35.581 ;
     RECT  9.648 35.371 44.946 35.581 ;
     RECT  2.34 35.581 44.946 35.597 ;
     RECT  26.676 35.597 44.946 36.239 ;
     RECT  2.34 35.597 25.686 36.347 ;
     RECT  4.968 36.347 25.686 36.355 ;
     RECT  26.712 36.239 44.946 36.475 ;
     RECT  4.968 36.355 25.758 37.003 ;
     RECT  26.712 36.475 45.234 37.049 ;
     RECT  2.34 36.347 4.158 37.129 ;
     RECT  4.968 37.003 25.83 37.129 ;
     RECT  2.34 37.129 25.83 37.201 ;
     RECT  2.34 37.201 25.974 37.319 ;
     RECT  2.34 37.319 25.686 37.589 ;
     RECT  2.34 37.589 15.858 38.395 ;
     RECT  16.596 37.589 25.506 38.395 ;
     RECT  26.712 37.049 44.946 38.443 ;
     RECT  2.34 38.395 25.506 38.777 ;
     RECT  26.604 38.443 44.946 39.091 ;
     RECT  26.532 39.091 44.946 39.209 ;
     RECT  26.532 39.209 44.802 39.901 ;
     RECT  2.415 38.777 25.506 40.325 ;
     RECT  25.488 40.325 25.506 40.369 ;
     RECT  26.316 39.901 44.802 40.369 ;
     RECT  2.415 40.325 24.75 40.445 ;
     RECT  25.488 40.369 44.802 40.559 ;
     RECT  25.488 40.559 44.658 40.739 ;
     RECT  25.488 40.739 44.586 40.865 ;
     RECT  2.415 40.445 24.714 41.021 ;
     RECT  25.488 40.865 35.514 41.611 ;
     RECT  36.288 40.865 44.586 41.611 ;
     RECT  15.588 41.021 24.714 41.639 ;
     RECT  25.488 41.611 44.586 41.639 ;
     RECT  15.588 41.639 24.534 41.791 ;
     RECT  15.48 41.791 24.534 41.909 ;
     RECT  2.415 41.021 14.742 41.953 ;
     RECT  15.48 41.909 24.426 41.953 ;
     RECT  25.488 41.639 44.478 42.017 ;
     RECT  25.488 42.017 31.482 42.053 ;
     RECT  2.415 41.953 24.426 42.089 ;
     RECT  32.292 42.017 44.478 42.215 ;
     RECT  32.292 42.215 44.046 42.287 ;
     RECT  32.292 42.287 43.974 42.359 ;
     RECT  2.415 42.089 15.786 42.835 ;
     RECT  16.524 42.089 24.426 42.835 ;
     RECT  25.488 42.053 31.41 42.961 ;
     RECT  32.292 42.359 43.866 42.961 ;
     RECT  25.488 42.961 43.866 43.105 ;
     RECT  25.308 43.105 43.866 43.133 ;
     RECT  2.415 42.835 24.426 43.259 ;
     RECT  2.415 43.259 23.274 43.601 ;
     RECT  2.415 43.601 23.238 43.637 ;
     RECT  2.415 43.637 23.166 43.709 ;
     RECT  25.308 43.133 43.83 43.799 ;
     RECT  2.415 43.709 23.022 43.853 ;
     RECT  2.415 43.853 21.762 43.871 ;
     RECT  25.308 43.799 43.506 44.069 ;
     RECT  2.415 43.871 21.042 44.105 ;
     RECT  2.415 44.105 20.97 44.141 ;
     RECT  25.308 44.069 43.254 44.141 ;
     RECT  2.415 44.141 20.934 44.147 ;
     RECT  2.415 44.147 19.494 44.177 ;
     RECT  25.308 44.141 41.598 44.177 ;
     RECT  20.232 44.147 20.934 44.213 ;
     RECT  42.372 44.141 43.254 44.213 ;
     RECT  25.308 44.177 41.346 44.249 ;
     RECT  42.66 44.213 43.254 44.249 ;
     RECT  24.015 43.259 24.426 44.311 ;
     RECT  25.308 44.249 41.274 44.311 ;
     RECT  24.015 44.311 41.274 44.339 ;
     RECT  42.66 44.249 42.678 44.339 ;
     RECT  2.415 44.177 19.422 44.375 ;
     RECT  25.056 44.339 25.074 44.381 ;
     RECT  10.152 44.375 19.422 44.411 ;
     RECT  32.004 44.339 41.274 44.411 ;
     RECT  10.152 44.411 18.954 44.447 ;
     RECT  10.368 44.447 18.954 44.483 ;
     RECT  20.232 44.213 20.466 44.483 ;
     RECT  32.004 44.411 41.094 44.483 ;
     RECT  2.415 44.375 8.154 44.609 ;
     RECT  23.004 43.853 23.022 44.609 ;
     RECT  25.956 44.339 31.23 44.609 ;
     RECT  3.564 44.609 8.154 44.645 ;
     RECT  25.956 44.609 28.35 44.645 ;
     RECT  29.196 44.609 31.086 44.645 ;
     RECT  3.564 44.645 5.382 44.681 ;
     RECT  27.36 44.645 28.35 44.681 ;
     RECT  10.368 44.483 17.694 44.717 ;
     RECT  27.36 44.681 27.378 44.717 ;
     RECT  4.14 44.681 5.382 44.753 ;
     RECT  10.368 44.717 14.454 44.753 ;
     RECT  15.408 44.717 17.694 44.753 ;
     RECT  18.504 44.483 18.897 44.753 ;
     RECT  6.12 44.645 8.154 44.789 ;
     RECT  10.368 44.753 11.322 44.789 ;
     RECT  15.552 44.753 17.694 44.789 ;
     RECT  6.12 44.789 8.097 44.879 ;
     RECT  10.44 44.789 11.322 44.879 ;
     RECT  12.06 44.753 14.454 44.879 ;
     RECT  15.624 44.789 17.694 44.879 ;
     RECT  25.956 44.645 26.622 44.879 ;
     RECT  29.196 44.645 30.942 44.879 ;
     RECT  32.004 44.483 40.497 44.879 ;
     RECT  4.86 44.753 5.274 44.915 ;
     RECT  6.768 44.879 6.786 44.915 ;
     RECT  10.908 44.879 11.322 44.915 ;
     RECT  14.436 44.879 14.454 44.915 ;
     RECT  15.624 44.879 15.822 44.915 ;
     RECT  16.776 44.879 17.694 44.915 ;
     RECT  25.956 44.879 25.974 44.915 ;
     RECT  5.112 44.915 5.274 44.951 ;
     RECT  8.928 44.375 9.414 44.951 ;
     RECT  12.132 44.879 13.698 44.951 ;
     RECT  32.004 44.879 32.634 44.951 ;
     RECT  12.132 44.951 12.258 44.987 ;
     RECT  15.768 44.915 15.786 44.987 ;
     RECT  32.616 44.951 32.634 44.987 ;
     RECT  33.66 44.879 40.497 44.987 ;
     RECT  16.812 44.915 17.694 45.005 ;
     RECT  5.22 44.951 5.238 45.023 ;
     RECT  12.132 44.987 12.15 45.023 ;
     RECT  13.104 44.951 13.497 45.023 ;
     RECT  16.812 45.005 17.442 45.023 ;
     RECT  29.415 44.879 30.762 45.023 ;
     RECT  34.02 44.987 34.038 45.023 ;
     RECT  30.708 45.023 30.726 45.059 ;
     RECT  34.815 44.987 40.497 45.059 ;
     RECT  2.415 44.609 2.697 45.107 ;
     RECT  7.815 44.879 8.097 45.107 ;
     RECT  13.215 45.023 13.497 45.107 ;
     RECT  18.615 44.753 18.897 45.107 ;
     RECT  24.015 44.339 24.297 45.107 ;
     RECT  29.415 45.023 29.697 45.107 ;
     RECT  36.9 45.059 40.497 45.107 ;
     RECT  34.815 45.059 36.162 45.149 ;
     RECT  36.9 45.107 40.305 45.149 ;
     RECT  9.144 44.951 9.414 45.185 ;
     RECT  34.815 45.149 35.262 45.185 ;
     RECT  36 45.149 36.018 45.185 ;
     RECT  36.9 45.149 37.35 45.185 ;
     RECT  38.16 45.149 39.186 45.185 ;
     RECT  34.815 45.185 35.226 45.221 ;
     RECT  36.936 45.185 37.35 45.221 ;
     RECT  9.252 45.185 9.414 45.257 ;
     RECT  37.332 45.221 37.35 45.257 ;
     RECT  9.396 45.257 9.414 45.293 ;
     RECT  38.16 45.185 38.178 45.293 ;
     RECT  2.415 45.107 2.505 45.377 ;
     RECT  7.815 45.107 7.905 45.377 ;
     RECT  13.215 45.107 13.305 45.377 ;
     RECT  18.615 45.107 18.705 45.377 ;
     RECT  24.015 45.107 24.105 45.377 ;
     RECT  29.415 45.107 29.505 45.377 ;
     RECT  34.815 45.221 34.905 45.377 ;
     RECT  40.215 45.149 40.305 45.377 ;
    LAYER M4 ;
     RECT  0.997 5.136 1.093 5.16 ;
     RECT  0.709 2.88 1.169 2.904 ;
     RECT  0.901 6.864 1.381 6.888 ;
     RECT  1.093 4.56 1.573 5.16 ;
     RECT  1.381 6.288 1.573 6.888 ;
     RECT  1.169 2.88 1.637 2.952 ;
     RECT  1.573 4.56 1.853 6.888 ;
     RECT  1.853 3.984 1.957 6.888 ;
     RECT  0.805 8.544 2.245 8.568 ;
     RECT  1.957 3.984 2.285 6.936 ;
     RECT  2.293 0.24 2.341 0.264 ;
     RECT  2.245 8.544 2.365 8.664 ;
     RECT  2.141 1.728 2.408 1.752 ;
     RECT  1.637 2.88 2.408 3 ;
     RECT  2.285 3.984 2.408 7.176 ;
     RECT  2.365 8.448 2.408 8.664 ;
     RECT  2.408 1.728 2.512 45.372 ;
     RECT  2.512 1.728 2.704 45.102 ;
     RECT  2.341 0.144 2.761 0.264 ;
     RECT  2.704 30.096 2.837 30.456 ;
     RECT  2.704 39.216 2.981 39.336 ;
     RECT  2.704 26.784 3.125 28.824 ;
     RECT  2.704 25.152 3.161 25.176 ;
     RECT  2.704 31.872 3.269 32.28 ;
     RECT  2.704 42.144 3.299 42.84 ;
     RECT  3.125 28.416 3.377 28.824 ;
     RECT  2.761 0.096 3.449 0.264 ;
     RECT  3.377 28.416 3.449 28.728 ;
     RECT  2.837 30.096 3.521 30.36 ;
     RECT  2.704 3.312 3.539 3.432 ;
     RECT  3.269 31.872 3.593 31.896 ;
     RECT  3.521 30.096 3.629 30.12 ;
     RECT  2.704 1.728 3.737 1.896 ;
     RECT  2.704 16.608 3.737 17.112 ;
     RECT  2.704 4.464 3.773 13.944 ;
     RECT  2.704 21.072 3.773 24.12 ;
     RECT  3.773 21.072 3.805 24.024 ;
     RECT  3.769 15.312 3.877 15.336 ;
     RECT  3.125 26.784 3.917 27.048 ;
     RECT  3.805 20.832 3.985 24.024 ;
     RECT  3.913 34.656 3.985 34.68 ;
     RECT  3.299 42.816 3.985 42.84 ;
     RECT  2.704 44.16 3.985 44.472 ;
     RECT  3.941 0.576 4.025 0.6 ;
     RECT  3.877 14.976 4.057 15.336 ;
     RECT  3.985 20.64 4.093 24.024 ;
     RECT  3.737 17.088 4.129 17.112 ;
     RECT  4.057 14.976 4.201 16.008 ;
     RECT  4.093 20.016 4.248 24.024 ;
     RECT  4.129 17.088 4.345 17.16 ;
     RECT  3.917 27.024 4.417 27.048 ;
     RECT  3.449 28.416 4.417 28.44 ;
     RECT  3.949 41.04 4.417 41.064 ;
     RECT  4.417 41.04 4.453 41.736 ;
     RECT  3.985 42.816 4.453 44.472 ;
     RECT  3.733 25.584 4.457 25.608 ;
     RECT  2.981 39.312 4.489 39.336 ;
     RECT  4.453 41.04 4.489 44.472 ;
     RECT  3.539 3.408 4.525 3.432 ;
     RECT  4.345 17.088 4.547 17.304 ;
     RECT  4.525 3.216 4.561 3.432 ;
     RECT  4.547 17.088 4.573 17.112 ;
     RECT  4.561 3.072 4.661 3.432 ;
     RECT  4.201 14.88 4.705 16.008 ;
     RECT  4.345 18.672 4.705 18.696 ;
     RECT  4.237 32.688 4.709 32.712 ;
     RECT  4.417 27.024 4.781 28.44 ;
     RECT  4.248 19.776 4.796 24.024 ;
     RECT  4.661 2.832 4.813 3.432 ;
     RECT  3.773 4.464 4.813 13.896 ;
     RECT  3.985 34.656 4.817 35.544 ;
     RECT  4.705 18.48 4.933 18.696 ;
     RECT  4.796 19.776 4.933 24.888 ;
     RECT  4.849 37.824 4.988 37.848 ;
     RECT  3.737 1.728 5.029 1.8 ;
     RECT  4.813 2.832 5.029 13.896 ;
     RECT  4.705 14.88 5.029 16.728 ;
     RECT  4.309 31.104 5.029 31.128 ;
     RECT  5.029 31.104 5.033 31.416 ;
     RECT  4.489 39.312 5.033 44.616 ;
     RECT  4.933 18.48 5.105 24.888 ;
     RECT  5.029 2.832 5.171 16.728 ;
     RECT  4.817 34.704 5.213 35.544 ;
     RECT  5.105 18.48 5.365 18.744 ;
     RECT  5.029 1.728 5.413 1.848 ;
     RECT  5.171 2.832 5.413 12.84 ;
     RECT  5.413 0.096 5.461 0.12 ;
     RECT  5.213 34.704 5.465 34.92 ;
     RECT  5.461 0.096 5.548 0.312 ;
     RECT  5.413 1.728 5.555 12.84 ;
     RECT  5.555 1.728 5.573 12.744 ;
     RECT  5.171 13.872 5.605 16.728 ;
     RECT  5.365 18.144 5.605 18.744 ;
     RECT  5.105 19.776 5.605 24.888 ;
     RECT  4.988 37.536 5.605 37.848 ;
     RECT  5.605 37.536 5.653 38.136 ;
     RECT  5.653 37.536 5.713 38.184 ;
     RECT  4.781 27.6 5.753 28.44 ;
     RECT  5.605 19.776 5.797 25.32 ;
     RECT  5.548 0.096 5.897 0.216 ;
     RECT  5.797 19.776 5.929 25.464 ;
     RECT  5.713 33.072 6.001 33.096 ;
     RECT  5.605 13.872 6.133 18.744 ;
     RECT  5.929 19.776 6.133 26.28 ;
     RECT  5.897 0.144 6.227 0.168 ;
     RECT  6.001 33.024 6.253 33.096 ;
     RECT  5.465 34.8 6.257 34.92 ;
     RECT  5.753 27.888 6.329 28.44 ;
     RECT  6.253 32.784 6.401 33.096 ;
     RECT  6.001 36 6.437 36.024 ;
     RECT  6.133 13.872 6.469 26.28 ;
     RECT  5.033 39.312 6.541 44.472 ;
     RECT  6.401 33.024 6.545 33.096 ;
     RECT  6.469 13.872 6.563 26.568 ;
     RECT  6.563 13.872 6.577 18.744 ;
     RECT  6.001 30.144 6.577 30.168 ;
     RECT  6.577 13.824 6.653 18.744 ;
     RECT  6.577 29.04 6.757 30.168 ;
     RECT  5.033 31.392 6.757 31.416 ;
     RECT  6.541 39.168 6.797 44.472 ;
     RECT  6.563 19.728 6.833 26.568 ;
     RECT  6.329 27.888 7.333 27.96 ;
     RECT  5.573 1.728 7.369 12.648 ;
     RECT  7.333 27.648 7.369 27.96 ;
     RECT  6.833 19.824 7.405 26.568 ;
     RECT  7.369 27.648 7.405 28.008 ;
     RECT  7.369 1.104 7.475 12.648 ;
     RECT  6.757 29.04 7.477 31.416 ;
     RECT  7.405 19.824 7.484 28.008 ;
     RECT  7.477 29.04 7.484 31.608 ;
     RECT  5.713 37.296 7.532 38.184 ;
     RECT  7.475 1.728 7.549 12.648 ;
     RECT  6.653 13.824 7.549 16.44 ;
     RECT  7.532 37.008 7.573 38.184 ;
     RECT  6.797 39.168 7.573 43.848 ;
     RECT  7.573 37.008 7.585 43.848 ;
     RECT  7.549 1.728 7.621 16.44 ;
     RECT  6.653 17.424 7.621 18.744 ;
     RECT  7.621 1.728 7.808 18.744 ;
     RECT  7.484 19.824 7.808 31.608 ;
     RECT  6.577 33.6 7.808 33.624 ;
     RECT  6.257 34.896 7.808 34.92 ;
     RECT  7.585 36.096 7.808 43.848 ;
     RECT  7.573 0.144 7.859 0.168 ;
     RECT  7.808 1.728 7.912 45.372 ;
     RECT  7.912 1.728 8.104 45.102 ;
     RECT  8.104 20.64 8.597 23.832 ;
     RECT  8.104 37.056 8.627 37.08 ;
     RECT  8.104 1.728 8.629 12.6 ;
     RECT  8.104 34.752 8.669 35.64 ;
     RECT  8.293 0.096 8.705 0.12 ;
     RECT  8.629 1.104 8.723 12.6 ;
     RECT  8.104 39.792 8.921 44.184 ;
     RECT  8.597 22.032 8.957 23.832 ;
     RECT  8.104 13.68 9.097 18.84 ;
     RECT  8.669 34.752 9.101 35.4 ;
     RECT  8.921 39.792 9.133 41.016 ;
     RECT  8.597 20.64 9.203 20.664 ;
     RECT  8.723 1.152 9.205 12.6 ;
     RECT  9.097 13.68 9.205 19.032 ;
     RECT  8.957 22.08 9.209 23.832 ;
     RECT  9.205 1.152 9.217 19.032 ;
     RECT  8.104 25.44 9.313 27.144 ;
     RECT  9.241 28.944 9.353 28.968 ;
     RECT  9.209 22.656 9.493 23.832 ;
     RECT  9.313 25.152 9.493 27.144 ;
     RECT  9.217 1.68 9.533 19.032 ;
     RECT  9.533 1.68 9.635 16.584 ;
     RECT  8.104 31.392 9.637 32.04 ;
     RECT  8.921 42 9.637 44.184 ;
     RECT  9.493 22.656 9.641 27.144 ;
     RECT  9.101 35.376 9.683 35.4 ;
     RECT  9.133 39.36 9.685 41.016 ;
     RECT  9.641 22.656 9.713 26.76 ;
     RECT  9.637 42 9.713 44.424 ;
     RECT  9.673 37.008 9.757 37.944 ;
     RECT  9.635 1.68 9.785 15.72 ;
     RECT  9.757 37.92 9.853 37.944 ;
     RECT  9.637 31.392 9.925 32.232 ;
     RECT  9.853 37.92 10.033 38.04 ;
     RECT  9.685 39.216 10.033 41.016 ;
     RECT  9.889 33.36 10.069 33.384 ;
     RECT  9.713 22.656 10.289 23.832 ;
     RECT  10.069 33.36 10.393 33.816 ;
     RECT  10.393 33.36 10.429 34.152 ;
     RECT  10.105 35.328 10.429 35.352 ;
     RECT  10.033 37.92 10.505 41.016 ;
     RECT  10.505 39.744 10.609 41.016 ;
     RECT  9.713 42.096 10.609 44.424 ;
     RECT  9.713 25.104 10.681 26.76 ;
     RECT  10.609 39.744 10.825 41.112 ;
     RECT  10.609 42.096 10.825 44.472 ;
     RECT  9.533 17.76 10.829 19.032 ;
     RECT  10.289 23.472 10.861 23.832 ;
     RECT  10.681 25.104 10.861 27.384 ;
     RECT  10.505 37.92 10.861 38.76 ;
     RECT  10.861 37.68 10.865 38.76 ;
     RECT  9.877 0.144 10.897 0.168 ;
     RECT  10.897 0.144 10.961 0.552 ;
     RECT  10.961 0.096 11.045 0.552 ;
     RECT  9.565 29.808 11.081 29.832 ;
     RECT  9.925 31.344 11.185 32.232 ;
     RECT  10.429 33.36 11.185 35.352 ;
     RECT  10.861 23.472 11.189 27.384 ;
     RECT  9.785 1.728 11.221 15.72 ;
     RECT  11.189 23.472 11.225 26.616 ;
     RECT  11.185 31.344 11.267 35.352 ;
     RECT  11.267 31.392 11.333 35.352 ;
     RECT  10.829 17.76 11.369 17.832 ;
     RECT  10.829 18.96 11.369 19.032 ;
     RECT  11.225 23.472 11.477 26.568 ;
     RECT  10.825 39.744 11.477 44.472 ;
     RECT  11.369 17.76 11.513 17.784 ;
     RECT  11.477 42 11.621 44.472 ;
     RECT  11.477 39.744 11.725 40.728 ;
     RECT  11.477 23.568 11.729 26.568 ;
     RECT  11.729 23.568 11.765 23.736 ;
     RECT  11.333 33.84 11.833 35.352 ;
     RECT  11.369 19.008 11.837 19.032 ;
     RECT  11.221 1.728 11.905 15.912 ;
     RECT  10.865 37.68 11.905 37.8 ;
     RECT  11.905 37.68 12.037 38.136 ;
     RECT  11.833 33.84 12.121 36.072 ;
     RECT  11.905 1.632 12.197 15.912 ;
     RECT  12.197 1.632 12.233 11.784 ;
     RECT  12.233 1.632 12.371 11.736 ;
     RECT  11.045 0.48 12.401 0.552 ;
     RECT  11.333 31.392 12.409 32.616 ;
     RECT  12.401 0.096 12.485 0.552 ;
     RECT  12.509 0.672 12.593 0.696 ;
     RECT  12.193 20.544 12.716 20.568 ;
     RECT  11.729 25.056 12.805 26.568 ;
     RECT  12.409 31.152 12.841 32.616 ;
     RECT  11.653 28.464 12.877 28.488 ;
     RECT  12.037 37.68 12.877 38.232 ;
     RECT  11.725 39.504 12.877 40.728 ;
     RECT  12.371 1.728 12.881 11.736 ;
     RECT  12.121 33.84 12.901 36.6 ;
     RECT  12.901 33.792 12.949 36.6 ;
     RECT  12.877 37.68 12.949 40.728 ;
     RECT  12.881 1.776 12.953 11.736 ;
     RECT  12.877 28.176 12.985 28.488 ;
     RECT  11.765 23.568 13.093 23.688 ;
     RECT  12.953 2.148 13.208 11.736 ;
     RECT  12.197 12.768 13.208 15.912 ;
     RECT  12.757 18.672 13.208 18.696 ;
     RECT  12.716 19.968 13.208 20.568 ;
     RECT  12.661 21.648 13.208 21.672 ;
     RECT  13.093 22.752 13.208 23.688 ;
     RECT  12.805 25.056 13.208 26.856 ;
     RECT  12.985 28.176 13.208 29.064 ;
     RECT  12.841 30.864 13.208 32.616 ;
     RECT  12.949 33.792 13.208 40.728 ;
     RECT  11.621 42.528 13.208 44.472 ;
     RECT  13.208 2.148 13.312 45.372 ;
     RECT  13.312 2.418 13.504 45.102 ;
     RECT  13.504 33.264 13.565 34.92 ;
     RECT  13.565 33.264 13.601 34.776 ;
     RECT  13.601 33.264 13.619 34.728 ;
     RECT  13.504 42.432 13.673 44.664 ;
     RECT  13.504 14.208 13.745 15.576 ;
     RECT  13.504 22.032 13.745 23.688 ;
     RECT  13.504 28.176 13.745 29.064 ;
     RECT  13.504 10.992 13.955 12.888 ;
     RECT  13.745 28.176 13.955 29.016 ;
     RECT  13.504 30.72 13.961 32.232 ;
     RECT  13.955 28.464 14.033 29.016 ;
     RECT  13.504 17.136 14.105 17.16 ;
     RECT  13.955 10.992 14.243 12.552 ;
     RECT  13.745 14.256 14.249 15.576 ;
     RECT  13.961 30.864 14.285 32.232 ;
     RECT  13.504 19.392 14.393 19.464 ;
     RECT  13.504 2.418 14.425 9.96 ;
     RECT  13.504 36.048 14.525 41.016 ;
     RECT  13.673 42.432 14.525 44.376 ;
     RECT  14.243 12 14.573 12.552 ;
     RECT  14.393 19.44 14.609 19.464 ;
     RECT  14.525 36.048 14.609 44.376 ;
     RECT  13.619 33.264 14.636 33.912 ;
     RECT  14.425 2.256 14.725 9.96 ;
     RECT  14.249 14.4 14.861 15.576 ;
     RECT  14.609 36.048 14.933 41.016 ;
     RECT  14.933 36.048 14.969 40.872 ;
     RECT  14.033 28.464 15.112 28.488 ;
     RECT  15.112 28.416 15.113 28.488 ;
     RECT  14.609 42.144 15.155 44.376 ;
     RECT  13.745 22.032 15.181 23.016 ;
     RECT  14.861 14.4 15.289 15 ;
     RECT  14.725 2.496 15.293 9.96 ;
     RECT  14.969 36.048 15.325 40.68 ;
     RECT  14.636 33.264 15.361 34.536 ;
     RECT  15.293 2.496 15.395 9.144 ;
     RECT  15.325 35.76 15.395 40.68 ;
     RECT  13.504 20.544 15.437 20.568 ;
     RECT  15.395 35.76 15.443 37.176 ;
     RECT  15.181 21.648 15.469 23.016 ;
     RECT  14.243 10.992 15.493 11.016 ;
     RECT  15.395 38.208 15.509 40.68 ;
     RECT  14.573 12 15.539 12.12 ;
     RECT  15.443 35.76 15.541 37.08 ;
     RECT  13.504 26.256 15.613 26.28 ;
     RECT  14.569 27.312 15.613 27.336 ;
     RECT  15.469 21.648 15.644 23.064 ;
     RECT  14.285 31.44 15.649 32.232 ;
     RECT  15.644 21.648 15.689 23.544 ;
     RECT  15.113 28.416 15.689 28.44 ;
     RECT  15.493 10.944 15.721 11.016 ;
     RECT  15.539 12 15.721 12.024 ;
     RECT  15.361 33.264 15.793 34.584 ;
     RECT  15.541 35.712 15.793 37.08 ;
     RECT  15.613 26.256 15.865 27.336 ;
     RECT  15.155 42.24 15.937 44.376 ;
     RECT  15.689 21.936 15.973 23.544 ;
     RECT  15.395 2.496 16.115 8.568 ;
     RECT  15.973 21.936 16.121 23.976 ;
     RECT  15.721 10.944 16.225 12.024 ;
     RECT  15.793 33.264 16.265 37.08 ;
     RECT  15.289 13.44 16.297 15 ;
     RECT  15.649 30.864 16.297 32.232 ;
     RECT  16.121 21.936 16.301 23.352 ;
     RECT  16.297 30.816 16.445 32.232 ;
     RECT  16.265 34.848 16.477 37.08 ;
     RECT  15.509 38.208 16.477 40.344 ;
     RECT  15.541 16.848 16.481 16.872 ;
     RECT  15.937 42.24 16.513 44.664 ;
     RECT  15.469 18.768 16.549 19.272 ;
     RECT  16.301 22.032 16.553 23.352 ;
     RECT  15.865 25.536 16.585 27.336 ;
     RECT  16.585 25.536 16.645 27.576 ;
     RECT  16.549 18.72 16.657 19.272 ;
     RECT  16.297 13.44 16.691 15.24 ;
     RECT  16.645 25.2 16.691 27.576 ;
     RECT  16.691 25.2 16.693 25.56 ;
     RECT  16.477 34.848 16.693 40.344 ;
     RECT  16.693 34.848 16.729 40.44 ;
     RECT  16.513 41.424 16.729 44.664 ;
     RECT  16.553 23.136 16.739 23.352 ;
     RECT  16.729 34.848 16.765 44.664 ;
     RECT  16.765 34.848 16.801 44.904 ;
     RECT  16.693 24.528 16.805 25.56 ;
     RECT  16.225 10.368 16.909 12.024 ;
     RECT  16.691 13.92 16.945 15.24 ;
     RECT  16.445 30.864 16.981 32.232 ;
     RECT  16.265 33.264 16.981 33.864 ;
     RECT  16.945 13.92 16.985 15.768 ;
     RECT  16.985 14.208 17.021 15.768 ;
     RECT  16.657 18.384 17.053 19.272 ;
     RECT  16.801 34.848 17.057 45 ;
     RECT  17.021 14.4 17.089 15.768 ;
     RECT  16.981 30.864 17.129 33.864 ;
     RECT  16.909 10.368 17.161 12.216 ;
     RECT  17.089 14.4 17.345 16.056 ;
     RECT  16.805 25.2 17.417 25.56 ;
     RECT  17.161 9.552 17.485 12.216 ;
     RECT  17.485 9.552 17.507 12.36 ;
     RECT  17.129 30.96 17.525 33.864 ;
     RECT  17.507 9.552 17.561 9.576 ;
     RECT  17.557 28.8 17.593 28.824 ;
     RECT  17.525 31.104 17.597 33.864 ;
     RECT  16.691 26.784 17.653 27.576 ;
     RECT  17.593 28.704 17.653 28.824 ;
     RECT  17.653 26.784 17.665 28.824 ;
     RECT  17.665 26.784 17.701 29.112 ;
     RECT  16.553 22.032 17.749 22.056 ;
     RECT  17.749 22.032 17.773 22.536 ;
     RECT  17.521 16.848 18.469 16.872 ;
     RECT  17.345 14.4 18.529 15.624 ;
     RECT  18.469 16.848 18.529 16.92 ;
     RECT  16.115 2.496 18.608 8.52 ;
     RECT  17.507 10.608 18.608 12.36 ;
     RECT  18.529 14.4 18.608 16.92 ;
     RECT  17.053 18.384 18.608 19.752 ;
     RECT  17.773 22.032 18.608 22.872 ;
     RECT  17.521 23.952 18.608 23.976 ;
     RECT  17.417 25.2 18.608 25.224 ;
     RECT  17.701 26.352 18.608 29.112 ;
     RECT  17.597 31.968 18.608 33.864 ;
     RECT  17.057 34.848 18.608 37.128 ;
     RECT  17.057 38.16 18.608 45 ;
     RECT  18.608 2.148 18.712 45.372 ;
     RECT  18.712 2.304 18.904 45.102 ;
     RECT  18.904 27.888 19.001 27.912 ;
     RECT  18.904 11.664 19.037 12.36 ;
     RECT  18.904 20.688 19.073 23.976 ;
     RECT  18.904 14.736 19.109 19.224 ;
     RECT  18.904 24.96 19.109 26.808 ;
     RECT  18.904 2.304 19.145 8.76 ;
     RECT  19.037 11.76 19.181 12.36 ;
     RECT  19.181 12.336 19.325 12.36 ;
     RECT  18.904 31.968 19.361 44.136 ;
     RECT  19.073 21.168 19.379 23.976 ;
     RECT  19.109 14.736 19.433 15.576 ;
     RECT  18.904 30.288 19.433 30.312 ;
     RECT  19.433 14.736 19.541 15 ;
     RECT  19.109 26.784 19.541 26.808 ;
     RECT  19.361 35.328 19.577 44.136 ;
     RECT  19.361 31.968 19.685 34.2 ;
     RECT  19.379 21.168 19.793 23.304 ;
     RECT  19.541 14.736 19.897 14.76 ;
     RECT  19.109 16.848 19.933 19.224 ;
     RECT  19.145 2.496 19.973 8.76 ;
     RECT  19.109 24.96 20.005 25.464 ;
     RECT  19.685 31.968 20.009 31.992 ;
     RECT  19.897 12.816 20.041 12.888 ;
     RECT  18.904 28.896 20.108 28.92 ;
     RECT  20.041 12.816 20.113 13.128 ;
     RECT  20.108 28.416 20.195 28.92 ;
     RECT  20.113 12.816 20.221 13.176 ;
     RECT  20.221 12.816 20.369 13.224 ;
     RECT  19.933 16.848 20.369 20.136 ;
     RECT  19.685 32.976 20.437 34.2 ;
     RECT  20.429 11.328 20.473 11.352 ;
     RECT  20.369 12.816 20.585 13.176 ;
     RECT  19.973 2.496 20.617 8.52 ;
     RECT  19.897 14.304 20.617 14.76 ;
     RECT  20.005 24.672 20.617 25.464 ;
     RECT  20.329 30.24 20.617 30.264 ;
     RECT  20.437 32.976 20.621 34.296 ;
     RECT  20.617 30.24 20.723 30.696 ;
     RECT  20.617 24.672 20.725 26.184 ;
     RECT  18.904 10.128 20.761 10.152 ;
     RECT  20.473 11.328 20.761 11.448 ;
     RECT  20.369 16.848 20.801 19.224 ;
     RECT  20.801 16.848 20.873 17.352 ;
     RECT  20.617 2.352 20.945 8.52 ;
     RECT  19.793 21.456 20.977 23.304 ;
     RECT  20.725 24.336 20.977 26.184 ;
     RECT  20.149 27.216 20.977 27.24 ;
     RECT  20.945 4.992 21.049 8.52 ;
     RECT  20.761 9.504 21.049 11.448 ;
     RECT  20.873 16.848 21.085 17.112 ;
     RECT  21.049 4.992 21.089 11.448 ;
     RECT  21.089 11.424 21.107 11.448 ;
     RECT  20.723 30.24 21.265 30.264 ;
     RECT  20.617 14.304 21.301 15.288 ;
     RECT  21.085 28.32 21.301 28.344 ;
     RECT  20.801 18.336 21.337 19.224 ;
     RECT  21.049 20.304 21.337 20.328 ;
     RECT  21.265 29.664 21.349 30.264 ;
     RECT  21.337 18.336 21.481 20.328 ;
     RECT  20.977 21.456 21.481 27.24 ;
     RECT  20.621 33.264 21.517 34.296 ;
     RECT  20.945 2.352 21.557 4.008 ;
     RECT  21.265 12.672 21.589 12.696 ;
     RECT  21.085 16.704 21.637 17.112 ;
     RECT  21.301 14.304 21.661 15.384 ;
     RECT  21.589 12.192 21.665 12.696 ;
     RECT  21.665 12.192 21.683 12.6 ;
     RECT  21.481 18.336 21.685 27.24 ;
     RECT  21.301 28.224 21.685 28.344 ;
     RECT  21.349 30.24 21.701 30.264 ;
     RECT  21.661 14.016 21.733 15.384 ;
     RECT  21.685 18.336 21.773 28.344 ;
     RECT  21.683 12.48 21.779 12.6 ;
     RECT  19.577 35.472 21.805 44.136 ;
     RECT  21.517 33.264 21.877 34.392 ;
     RECT  21.805 35.424 21.877 44.136 ;
     RECT  21.733 13.68 21.881 15.384 ;
     RECT  21.637 16.56 21.913 17.112 ;
     RECT  21.773 18.336 21.913 27.24 ;
     RECT  21.913 30.576 21.925 30.6 ;
     RECT  21.913 16.56 21.953 27.24 ;
     RECT  21.881 13.68 21.989 14.328 ;
     RECT  22.021 28.416 22.069 28.44 ;
     RECT  21.953 20.064 22.097 27.24 ;
     RECT  22.069 28.416 22.115 28.68 ;
     RECT  21.089 4.992 22.133 10.344 ;
     RECT  21.953 16.56 22.165 18.84 ;
     RECT  22.165 15.6 22.205 18.84 ;
     RECT  22.205 16.608 22.211 18.84 ;
     RECT  22.097 20.16 22.277 27.24 ;
     RECT  21.877 33.264 22.277 44.136 ;
     RECT  22.115 28.56 22.309 28.68 ;
     RECT  22.133 8.784 22.313 10.344 ;
     RECT  22.211 18.336 22.349 18.84 ;
     RECT  22.277 33.552 22.355 44.136 ;
     RECT  21.925 30.576 22.364 31.32 ;
     RECT  22.355 33.552 22.421 43.848 ;
     RECT  22.364 30.576 22.451 31.56 ;
     RECT  22.313 8.784 22.529 10.152 ;
     RECT  22.309 28.56 22.547 28.776 ;
     RECT  22.349 18.432 22.709 18.84 ;
     RECT  22.277 20.304 22.741 27.24 ;
     RECT  21.779 12.576 22.745 12.6 ;
     RECT  21.557 2.496 22.813 4.008 ;
     RECT  22.421 33.552 22.835 43.56 ;
     RECT  22.205 15.6 22.853 15.624 ;
     RECT  22.835 33.552 22.853 43.368 ;
     RECT  22.853 35.28 22.925 43.368 ;
     RECT  21.989 13.872 23.173 14.328 ;
     RECT  23.173 13.632 23.353 14.328 ;
     RECT  22.853 33.552 23.365 33.864 ;
     RECT  22.529 9.936 23.461 10.152 ;
     RECT  22.741 20.304 23.713 27.336 ;
     RECT  22.813 2.352 23.749 4.008 ;
     RECT  22.133 4.992 23.749 7.656 ;
     RECT  23.461 9.936 23.749 10.632 ;
     RECT  22.709 18.528 23.749 18.84 ;
     RECT  23.713 19.872 23.749 27.336 ;
     RECT  22.547 28.56 23.749 28.728 ;
     RECT  22.777 12.192 23.821 12.552 ;
     RECT  23.821 12.048 23.857 12.552 ;
     RECT  23.353 13.632 23.857 15 ;
     RECT  22.211 16.608 23.857 17.16 ;
     RECT  23.857 12.048 23.893 15 ;
     RECT  23.857 15.984 23.893 17.16 ;
     RECT  23.749 2.352 24.008 7.656 ;
     RECT  23.749 9.072 24.008 10.632 ;
     RECT  23.893 12.048 24.008 17.16 ;
     RECT  23.749 18.528 24.008 28.728 ;
     RECT  22.451 30.576 24.008 31.368 ;
     RECT  23.365 33.456 24.008 33.864 ;
     RECT  22.925 35.28 24.008 42.312 ;
     RECT  22.925 43.344 24.008 43.368 ;
     RECT  24.008 2.148 24.112 45.372 ;
     RECT  24.112 2.352 24.304 45.102 ;
     RECT  24.304 30.384 24.419 33.144 ;
     RECT  24.419 30.48 24.473 33.144 ;
     RECT  24.304 38.976 24.473 41.4 ;
     RECT  24.304 8.448 24.509 24.168 ;
     RECT  24.473 38.976 24.509 40.584 ;
     RECT  24.509 13.584 24.545 19.32 ;
     RECT  24.509 20.304 24.545 24.168 ;
     RECT  24.545 13.584 24.553 17.88 ;
     RECT  24.509 38.976 24.617 40.44 ;
     RECT  24.553 13.584 24.653 15.384 ;
     RECT  24.473 30.576 24.761 33.144 ;
     RECT  24.617 39.888 24.761 40.44 ;
     RECT  24.545 20.304 24.797 23.88 ;
     RECT  24.797 23.28 24.869 23.88 ;
     RECT  24.304 25.2 24.869 25.368 ;
     RECT  24.761 39.888 24.913 39.912 ;
     RECT  24.304 34.752 25.013 37.656 ;
     RECT  24.761 30.864 25.121 33.144 ;
     RECT  25.121 31.152 25.193 33.144 ;
     RECT  24.304 26.496 25.229 28.728 ;
     RECT  24.304 2.352 25.297 2.808 ;
     RECT  24.304 3.84 25.297 7.176 ;
     RECT  25.193 31.68 25.337 33.144 ;
     RECT  25.013 36.288 25.409 37.656 ;
     RECT  24.869 25.344 25.441 25.368 ;
     RECT  25.229 26.496 25.441 27.96 ;
     RECT  24.509 8.448 25.445 12.552 ;
     RECT  25.337 31.776 25.481 33.144 ;
     RECT  25.441 25.344 25.553 27.96 ;
     RECT  25.481 33.12 25.553 33.144 ;
     RECT  24.653 13.584 25.621 15.288 ;
     RECT  24.553 16.56 25.621 17.88 ;
     RECT  25.445 9.792 25.733 11.448 ;
     RECT  25.445 12.528 25.981 12.552 ;
     RECT  25.621 13.584 25.981 17.88 ;
     RECT  25.733 10.128 25.985 11.448 ;
     RECT  25.553 25.584 26.021 27.96 ;
     RECT  25.981 12.528 26.053 17.88 ;
     RECT  24.545 19.296 26.053 19.32 ;
     RECT  26.053 12.528 26.089 19.32 ;
     RECT  24.797 20.304 26.089 22.056 ;
     RECT  26.089 12.528 26.093 22.056 ;
     RECT  25.013 34.752 26.129 34.776 ;
     RECT  26.093 17.04 26.165 22.056 ;
     RECT  26.125 33.504 26.197 33.528 ;
     RECT  25.297 2.352 26.237 7.176 ;
     RECT  25.873 43.296 26.237 43.32 ;
     RECT  26.197 33.504 26.243 33.816 ;
     RECT  26.021 26.496 26.273 27.96 ;
     RECT  25.481 31.776 26.345 31.8 ;
     RECT  25.409 36.288 26.348 37.032 ;
     RECT  26.053 42.144 26.521 42.168 ;
     RECT  26.237 2.496 26.557 7.176 ;
     RECT  25.445 8.448 26.557 8.808 ;
     RECT  26.593 39.84 26.629 39.864 ;
     RECT  25.985 10.32 26.701 11.448 ;
     RECT  26.093 12.528 26.701 16.008 ;
     RECT  26.557 2.496 26.737 8.808 ;
     RECT  26.348 35.568 26.771 37.032 ;
     RECT  26.629 39.072 26.771 39.864 ;
     RECT  26.165 19.296 26.773 22.056 ;
     RECT  26.305 43.248 26.777 43.272 ;
     RECT  26.771 39.36 26.813 39.864 ;
     RECT  26.521 42.144 26.845 42.216 ;
     RECT  26.737 2.496 27.025 9.048 ;
     RECT  26.701 10.32 27.025 16.008 ;
     RECT  26.773 19.296 27.205 22.248 ;
     RECT  24.869 23.28 27.205 23.832 ;
     RECT  27.025 2.496 27.241 16.008 ;
     RECT  26.165 17.04 27.241 17.736 ;
     RECT  26.243 33.792 27.241 33.816 ;
     RECT  27.241 33.6 27.277 34.392 ;
     RECT  27.241 2.496 27.313 17.736 ;
     RECT  26.881 39.888 27.425 40.632 ;
     RECT  26.845 42.144 27.425 43.128 ;
     RECT  27.205 19.296 27.533 23.832 ;
     RECT  27.313 2.352 27.569 17.736 ;
     RECT  26.809 25.056 27.601 25.08 ;
     RECT  26.273 26.496 27.601 27.096 ;
     RECT  27.533 19.344 27.965 23.832 ;
     RECT  27.277 33.6 28.033 35.448 ;
     RECT  26.771 36.48 28.033 37.032 ;
     RECT  27.637 38.256 28.033 38.28 ;
     RECT  27.425 42.144 28.105 42.216 ;
     RECT  27.569 2.352 28.109 17.208 ;
     RECT  28.033 33.6 28.177 37.032 ;
     RECT  27.601 25.056 28.181 27.096 ;
     RECT  28.177 33.6 28.285 37.128 ;
     RECT  27.965 21.936 28.357 23.832 ;
     RECT  27.925 32.016 28.357 32.04 ;
     RECT  28.033 38.256 28.357 38.376 ;
     RECT  28.105 41.952 28.357 42.216 ;
     RECT  28.109 2.496 28.397 17.208 ;
     RECT  28.357 21.936 28.465 23.928 ;
     RECT  28.181 25.056 28.465 25.176 ;
     RECT  28.177 43.296 28.573 43.32 ;
     RECT  24.304 44.352 28.573 44.376 ;
     RECT  28.609 30.288 28.789 30.312 ;
     RECT  28.789 30.288 29.084 30.888 ;
     RECT  28.357 31.872 29.084 32.04 ;
     RECT  29.084 30.288 29.149 32.04 ;
     RECT  28.285 33.552 29.149 37.128 ;
     RECT  27.425 39.888 29.149 39.912 ;
     RECT  28.357 41.424 29.149 42.216 ;
     RECT  28.573 43.296 29.149 44.376 ;
     RECT  28.181 26.496 29.185 27.096 ;
     RECT  29.149 30.288 29.185 32.328 ;
     RECT  29.149 33.36 29.185 37.128 ;
     RECT  28.357 38.256 29.221 38.664 ;
     RECT  29.221 28.992 29.257 29.016 ;
     RECT  29.185 30.288 29.257 37.128 ;
     RECT  29.149 39.888 29.269 44.376 ;
     RECT  28.397 2.496 29.408 9.864 ;
     RECT  28.397 11.136 29.408 17.208 ;
     RECT  27.965 19.344 29.408 20.376 ;
     RECT  28.465 21.936 29.408 25.176 ;
     RECT  29.185 26.304 29.408 27.096 ;
     RECT  29.257 28.992 29.408 37.128 ;
     RECT  29.221 38.208 29.408 38.664 ;
     RECT  29.269 39.888 29.408 44.472 ;
     RECT  29.408 2.148 29.512 45.372 ;
     RECT  29.512 2.256 29.704 45.102 ;
     RECT  29.704 2.256 29.765 16.392 ;
     RECT  29.765 2.256 29.873 7.368 ;
     RECT  29.704 26.304 29.873 27.096 ;
     RECT  29.704 21.744 29.909 24.504 ;
     RECT  29.704 30.576 29.909 32.52 ;
     RECT  29.704 19.776 29.939 20.76 ;
     RECT  29.704 39.552 29.945 40.296 ;
     RECT  29.765 8.448 29.981 16.392 ;
     RECT  29.909 21.792 30.017 24.504 ;
     RECT  29.909 30.576 30.017 32.328 ;
     RECT  29.981 8.448 30.241 16.344 ;
     RECT  30.017 30.96 30.269 32.328 ;
     RECT  29.704 37.632 30.269 37.944 ;
     RECT  29.704 33.552 30.449 35.448 ;
     RECT  29.873 2.256 30.557 3.96 ;
     RECT  30.241 15.984 30.563 16.344 ;
     RECT  30.269 30.96 30.803 31.368 ;
     RECT  30.269 37.92 30.805 37.944 ;
     RECT  30.557 2.256 30.809 2.856 ;
     RECT  30.803 30.96 30.809 31.224 ;
     RECT  29.704 18.192 30.841 18.264 ;
     RECT  29.873 4.992 30.908 7.368 ;
     RECT  30.241 8.448 30.908 14.472 ;
     RECT  29.939 19.776 30.913 20.328 ;
     RECT  30.805 37.92 30.985 38.76 ;
     RECT  30.908 4.992 30.995 14.472 ;
     RECT  29.704 28.992 31.021 29.544 ;
     RECT  30.809 30.96 31.021 30.984 ;
     RECT  30.995 8.448 31.025 14.472 ;
     RECT  30.017 21.792 31.057 24.216 ;
     RECT  31.057 21.792 31.093 25.176 ;
     RECT  29.704 41.424 31.097 44.472 ;
     RECT  30.985 37.92 31.133 38.952 ;
     RECT  31.133 38.928 31.241 38.952 ;
     RECT  31.097 41.424 31.277 43.896 ;
     RECT  30.995 4.992 31.283 7.368 ;
     RECT  30.913 19.776 31.309 20.376 ;
     RECT  31.093 21.744 31.309 25.176 ;
     RECT  31.309 19.776 31.313 25.176 ;
     RECT  31.021 28.992 31.345 30.984 ;
     RECT  31.025 8.448 31.385 13.656 ;
     RECT  31.313 24.912 31.417 25.176 ;
     RECT  31.283 4.992 31.421 6.888 ;
     RECT  31.385 8.448 31.421 8.472 ;
     RECT  30.841 18.192 31.421 18.792 ;
     RECT  30.557 3.888 31.493 3.96 ;
     RECT  30.563 16.32 31.532 16.344 ;
     RECT  31.309 14.784 31.561 14.808 ;
     RECT  31.532 15.84 31.561 16.344 ;
     RECT  31.385 10.368 31.565 13.656 ;
     RECT  31.421 18.432 31.597 18.792 ;
     RECT  31.313 19.776 31.597 23.928 ;
     RECT  31.345 28.416 31.961 30.984 ;
     RECT  31.417 24.912 31.993 25.416 ;
     RECT  29.873 26.496 31.993 27.096 ;
     RECT  30.809 2.592 32.029 2.856 ;
     RECT  31.493 3.888 32.029 3.912 ;
     RECT  31.561 14.784 32.06 16.344 ;
     RECT  32.06 14.784 32.065 16.824 ;
     RECT  29.945 40.272 32.101 40.296 ;
     RECT  31.277 41.424 32.101 41.928 ;
     RECT  32.065 14.784 32.147 17.352 ;
     RECT  31.565 10.848 32.245 13.656 ;
     RECT  32.147 14.784 32.285 16.008 ;
     RECT  31.277 43.104 32.321 43.896 ;
     RECT  31.133 37.92 32.389 37.944 ;
     RECT  32.285 15.12 32.393 16.008 ;
     RECT  31.421 4.992 32.417 6.792 ;
     RECT  32.245 10.848 32.429 13.704 ;
     RECT  32.147 17.088 32.435 17.352 ;
     RECT  32.101 40.272 32.461 41.928 ;
     RECT  32.321 43.104 32.461 43.656 ;
     RECT  31.993 33.024 32.485 33.048 ;
     RECT  30.449 34.368 32.485 35.448 ;
     RECT  31.961 28.464 32.492 30.984 ;
     RECT  32.029 2.592 32.497 3.912 ;
     RECT  32.417 4.992 32.501 6.888 ;
     RECT  31.597 18.432 32.501 23.928 ;
     RECT  32.501 18.432 32.531 19.8 ;
     RECT  32.485 33.024 32.531 35.448 ;
     RECT  32.435 17.328 32.569 17.352 ;
     RECT  32.531 18.432 32.569 19.368 ;
     RECT  32.501 4.992 32.573 6.264 ;
     RECT  31.993 24.912 32.573 27.096 ;
     RECT  32.492 28.464 32.579 31.464 ;
     RECT  32.501 21.12 32.605 23.928 ;
     RECT  32.573 24.912 32.605 25.032 ;
     RECT  32.429 11.184 32.681 13.704 ;
     RECT  32.461 40.272 32.681 43.656 ;
     RECT  32.579 28.464 32.723 30.792 ;
     RECT  32.605 7.968 32.785 7.992 ;
     RECT  32.281 36.672 32.789 36.696 ;
     RECT  32.531 33.552 32.825 35.448 ;
     RECT  32.681 40.272 32.861 43.176 ;
     RECT  32.497 2.592 32.893 3.96 ;
     RECT  32.573 4.992 32.893 6.12 ;
     RECT  32.569 17.328 32.897 19.368 ;
     RECT  32.681 11.376 32.933 13.704 ;
     RECT  32.861 40.272 32.933 43.128 ;
     RECT  32.389 37.92 33.113 38.136 ;
     RECT  32.573 26.592 33.181 27.096 ;
     RECT  32.897 17.328 33.257 18.456 ;
     RECT  32.825 34.56 33.325 35.448 ;
     RECT  32.825 33.552 33.329 33.576 ;
     RECT  32.393 15.12 33.356 15.576 ;
     RECT  33.356 14.736 33.443 15.576 ;
     RECT  33.443 15.504 33.469 15.576 ;
     RECT  32.605 21.12 33.505 25.032 ;
     RECT  33.325 34.56 33.545 36.072 ;
     RECT  32.893 2.592 33.637 6.12 ;
     RECT  33.505 20.976 33.649 25.032 ;
     RECT  33.257 17.616 33.653 18.456 ;
     RECT  33.649 20.64 33.685 25.032 ;
     RECT  33.637 2.256 33.689 6.12 ;
     RECT  32.933 11.376 33.721 11.4 ;
     RECT  33.689 4.368 33.724 6.12 ;
     RECT  33.181 26.592 33.733 27.384 ;
     RECT  32.723 28.512 33.733 30.792 ;
     RECT  33.733 26.592 33.779 30.792 ;
     RECT  33.545 35.424 33.779 36.072 ;
     RECT  33.721 11.184 33.793 11.4 ;
     RECT  32.785 7.92 33.833 7.992 ;
     RECT  33.181 39.024 33.877 39.048 ;
     RECT  32.933 40.272 33.937 40.296 ;
     RECT  33.289 44.736 33.973 44.76 ;
     RECT  33.793 10.272 34.021 11.4 ;
     RECT  32.933 12.816 34.021 13.704 ;
     RECT  33.937 40.272 34.045 40.344 ;
     RECT  32.933 41.424 34.045 43.128 ;
     RECT  33.779 35.472 34.117 36.072 ;
     RECT  33.877 39.024 34.153 39.096 ;
     RECT  34.045 40.272 34.153 43.128 ;
     RECT  33.685 20.64 34.165 25.272 ;
     RECT  33.779 26.592 34.165 29.4 ;
     RECT  34.165 20.64 34.297 29.4 ;
     RECT  33.724 5.088 34.453 6.12 ;
     RECT  34.369 9.072 34.513 9.096 ;
     RECT  34.021 10.272 34.513 13.704 ;
     RECT  33.469 15.504 34.513 15.768 ;
     RECT  34.453 5.088 34.549 6.6 ;
     RECT  33.833 7.968 34.549 7.992 ;
     RECT  34.513 8.976 34.549 13.704 ;
     RECT  34.513 33.648 34.549 33.672 ;
     RECT  34.549 7.968 34.621 13.704 ;
     RECT  33.689 2.256 34.657 2.808 ;
     RECT  34.549 33.024 34.657 33.672 ;
     RECT  34.117 35.472 34.693 36.312 ;
     RECT  34.513 15.504 34.729 16.008 ;
     RECT  34.549 5.088 34.765 6.792 ;
     RECT  34.657 32.592 34.765 33.672 ;
     RECT  34.693 35.472 34.765 36.36 ;
     RECT  33.779 30.768 34.801 30.792 ;
     RECT  34.765 31.92 34.801 33.672 ;
     RECT  33.973 44.544 34.801 44.76 ;
     RECT  34.657 2.256 34.808 3.432 ;
     RECT  34.765 5.088 34.808 6.84 ;
     RECT  34.621 7.968 34.808 14.472 ;
     RECT  34.729 15.456 34.808 16.008 ;
     RECT  33.653 17.856 34.808 18.456 ;
     RECT  34.297 20.16 34.808 29.4 ;
     RECT  34.801 30.768 34.808 33.672 ;
     RECT  34.765 34.704 34.808 36.36 ;
     RECT  33.325 37.68 34.808 37.704 ;
     RECT  34.153 39.024 34.808 43.128 ;
     RECT  34.801 44.448 34.808 44.76 ;
     RECT  34.808 2.148 34.912 45.372 ;
     RECT  34.912 2.418 35.104 45.102 ;
     RECT  35.104 7.968 35.165 29.112 ;
     RECT  35.104 6.672 35.237 6.888 ;
     RECT  35.165 14.448 35.267 29.112 ;
     RECT  35.104 44.304 35.273 44.664 ;
     RECT  35.104 5.232 35.309 5.592 ;
     RECT  35.165 7.968 35.309 13.464 ;
     RECT  35.273 44.304 35.381 44.328 ;
     RECT  35.309 7.968 35.489 9.096 ;
     RECT  35.267 20.352 35.641 29.112 ;
     RECT  35.104 31.104 35.741 31.944 ;
     RECT  35.741 31.104 35.813 31.8 ;
     RECT  35.104 33.024 35.885 34.824 ;
     RECT  35.309 10.32 36.124 13.464 ;
     RECT  35.104 2.784 36.133 3.72 ;
     RECT  36.124 10.32 36.145 11.448 ;
     RECT  35.104 39.024 36.169 43.032 ;
     RECT  35.309 5.568 36.179 5.592 ;
     RECT  36.145 10.32 36.277 11.4 ;
     RECT  35.885 34.08 36.277 34.824 ;
     RECT  35.104 36.048 36.277 36.36 ;
     RECT  36.277 34.08 36.323 36.36 ;
     RECT  36.323 34.08 36.353 34.152 ;
     RECT  35.237 6.672 36.385 6.84 ;
     RECT  35.489 7.968 36.385 8.712 ;
     RECT  36.169 38.4 36.385 43.032 ;
     RECT  36.323 35.616 36.421 36.36 ;
     RECT  36.385 37.584 36.421 43.032 ;
     RECT  35.813 31.104 36.457 31.128 ;
     RECT  36.421 35.616 36.515 43.032 ;
     RECT  36.133 2.784 36.533 3.864 ;
     RECT  36.515 38.4 36.563 43.032 ;
     RECT  35.885 33.024 36.569 33.048 ;
     RECT  35.641 20.352 36.605 28.536 ;
     RECT  36.277 9.696 36.641 11.4 ;
     RECT  36.563 38.4 36.641 40.632 ;
     RECT  36.563 41.856 36.745 43.032 ;
     RECT  36.529 44.448 36.745 44.472 ;
     RECT  36.637 32.976 36.749 33 ;
     RECT  36.457 31.008 36.773 31.128 ;
     RECT  36.515 35.616 36.821 36.888 ;
     RECT  36.773 30.192 36.857 31.128 ;
     RECT  36.641 10.08 36.893 11.4 ;
     RECT  36.124 12.528 36.901 13.464 ;
     RECT  35.267 14.448 36.901 19.368 ;
     RECT  36.353 34.08 36.965 34.104 ;
     RECT  36.821 36.144 36.965 36.888 ;
     RECT  36.641 38.448 37.001 40.632 ;
     RECT  37.001 38.448 37.109 40.296 ;
     RECT  36.745 41.856 37.109 44.472 ;
     RECT  36.893 11.184 37.141 11.4 ;
     RECT  36.901 12.528 37.141 19.368 ;
     RECT  36.533 2.784 37.181 3.096 ;
     RECT  37.141 5.136 37.321 5.16 ;
     RECT  36.385 6.672 37.357 8.712 ;
     RECT  37.357 6.288 37.379 8.712 ;
     RECT  36.857 30.528 37.433 31.128 ;
     RECT  37.321 4.944 37.537 5.16 ;
     RECT  37.379 6.288 37.537 6.84 ;
     RECT  37.537 4.944 37.667 6.84 ;
     RECT  37.379 7.92 37.789 8.712 ;
     RECT  37.181 2.832 37.825 3.096 ;
     RECT  37.667 4.944 37.865 6.744 ;
     RECT  37.433 30.528 37.865 30.552 ;
     RECT  37.109 41.904 37.916 44.472 ;
     RECT  37.825 2.832 37.973 3.96 ;
     RECT  36.605 20.352 38.009 27.912 ;
     RECT  36.965 36.144 38.041 36.792 ;
     RECT  37.916 41.904 38.053 45.048 ;
     RECT  36.893 10.08 38.101 10.104 ;
     RECT  37.141 11.184 38.101 19.368 ;
     RECT  37.109 38.448 38.113 40.152 ;
     RECT  38.101 10.08 38.149 19.368 ;
     RECT  38.009 20.352 38.149 26.808 ;
     RECT  38.041 36.144 38.149 36.888 ;
     RECT  38.113 38.208 38.149 40.152 ;
     RECT  38.149 36.144 38.185 36.936 ;
     RECT  38.149 38.112 38.185 40.152 ;
     RECT  38.053 41.904 38.185 45.288 ;
     RECT  38.185 35.76 38.189 45.288 ;
     RECT  38.149 10.08 38.225 26.808 ;
     RECT  38.225 10.08 38.233 10.296 ;
     RECT  37.789 7.92 38.257 9.048 ;
     RECT  38.233 10.08 38.257 10.2 ;
     RECT  37.285 29.04 38.401 29.064 ;
     RECT  37.973 2.832 38.477 2.856 ;
     RECT  38.225 11.28 38.549 26.808 ;
     RECT  37.973 3.936 38.617 3.96 ;
     RECT  38.009 27.888 38.653 27.912 ;
     RECT  38.401 28.944 38.653 29.064 ;
     RECT  38.549 22.128 38.657 26.808 ;
     RECT  37.069 32.592 38.725 32.664 ;
     RECT  38.401 34.512 38.725 34.536 ;
     RECT  38.545 30.72 38.764 31.416 ;
     RECT  38.189 35.76 38.765 44.904 ;
     RECT  37.865 5.616 38.833 6.744 ;
     RECT  38.653 27.888 38.837 29.064 ;
     RECT  38.657 22.128 38.909 24.456 ;
     RECT  38.549 11.28 38.915 20.904 ;
     RECT  38.833 5.616 38.917 6.84 ;
     RECT  38.915 11.28 38.945 19.416 ;
     RECT  38.725 32.592 38.977 34.536 ;
     RECT  38.945 18.816 38.981 19.416 ;
     RECT  38.765 38.112 38.981 44.904 ;
     RECT  38.981 39.216 39.004 44.904 ;
     RECT  38.981 38.112 39.017 38.232 ;
     RECT  38.909 22.128 39.053 23.928 ;
     RECT  38.765 35.76 39.053 36.936 ;
     RECT  39.053 36 39.089 36.936 ;
     RECT  39.053 23.856 39.125 23.928 ;
     RECT  38.617 3.936 39.193 4.248 ;
     RECT  38.917 5.616 39.193 6.312 ;
     RECT  38.945 11.28 39.197 17.688 ;
     RECT  39.197 11.28 39.233 16.392 ;
     RECT  38.257 7.92 39.301 10.2 ;
     RECT  39.233 11.28 39.301 13.032 ;
     RECT  39.193 3.936 39.625 6.312 ;
     RECT  39.053 22.128 39.841 22.824 ;
     RECT  39.841 2.544 39.985 2.568 ;
     RECT  39.625 3.696 39.985 6.312 ;
     RECT  39.017 38.112 40.021 38.136 ;
     RECT  40.021 37.968 40.057 38.136 ;
     RECT  39.004 39.216 40.057 44.088 ;
     RECT  39.985 2.544 40.069 6.312 ;
     RECT  39.301 7.392 40.069 13.032 ;
     RECT  40.069 2.544 40.208 13.032 ;
     RECT  39.233 14.4 40.208 16.392 ;
     RECT  39.197 17.664 40.208 17.688 ;
     RECT  38.981 18.864 40.208 19.416 ;
     RECT  38.915 20.88 40.208 20.904 ;
     RECT  39.841 22.032 40.208 22.824 ;
     RECT  39.925 24.48 40.208 24.504 ;
     RECT  38.657 25.68 40.208 26.808 ;
     RECT  38.837 28.608 40.208 29.064 ;
     RECT  38.764 31.392 40.208 31.416 ;
     RECT  38.977 32.592 40.208 34.68 ;
     RECT  39.089 36 40.208 36.408 ;
     RECT  40.057 37.968 40.208 44.088 ;
     RECT  40.208 2.148 40.312 45.372 ;
     RECT  40.312 2.418 40.504 45.102 ;
     RECT  40.504 14.4 40.565 17.688 ;
     RECT  40.504 20.88 40.565 23.064 ;
     RECT  40.565 14.4 40.601 16.392 ;
     RECT  40.565 22.752 40.601 23.064 ;
     RECT  40.504 37.68 40.681 44.088 ;
     RECT  40.504 2.544 40.739 13.368 ;
     RECT  40.681 43.344 40.835 44.088 ;
     RECT  40.057 0.144 40.849 0.168 ;
     RECT  40.504 30.144 40.925 36.696 ;
     RECT  40.504 26.304 40.931 27.384 ;
     RECT  40.925 35.664 40.931 36.696 ;
     RECT  40.601 22.752 40.933 22.776 ;
     RECT  40.601 14.4 41.033 15.864 ;
     RECT  40.925 30.144 41.033 34.68 ;
     RECT  40.931 35.664 41.141 36.312 ;
     RECT  41.033 30.384 41.321 34.68 ;
     RECT  40.504 18.768 41.497 19.368 ;
     RECT  41.497 18.768 41.537 19.416 ;
     RECT  41.033 15.84 41.603 15.864 ;
     RECT  40.565 21.648 41.681 21.672 ;
     RECT  40.681 37.68 41.789 42.264 ;
     RECT  40.835 43.344 41.897 43.368 ;
     RECT  41.537 19.392 41.929 19.416 ;
     RECT  40.931 26.304 41.969 26.328 ;
     RECT  40.739 2.88 42.14 13.368 ;
     RECT  40.931 27.36 42.14 27.384 ;
     RECT  42.14 25.44 42.181 25.464 ;
     RECT  41.893 1.68 42.217 1.704 ;
     RECT  40.849 0.144 42.253 0.552 ;
     RECT  42.217 1.68 42.253 1.752 ;
     RECT  42.14 2.832 42.253 13.368 ;
     RECT  42.14 27.36 42.289 27.912 ;
     RECT  41.321 30.384 42.289 34.248 ;
     RECT  41.789 41.568 42.289 42.264 ;
     RECT  42.181 24.48 42.293 25.464 ;
     RECT  41.141 35.664 42.361 36.12 ;
     RECT  42.289 41.568 42.401 42.696 ;
     RECT  42.217 22.464 42.421 22.488 ;
     RECT  41.789 37.68 42.437 40.44 ;
     RECT  41.929 19.392 42.517 19.656 ;
     RECT  42.289 30.288 42.541 34.248 ;
     RECT  42.361 35.664 42.541 36.6 ;
     RECT  42.253 0.096 42.565 0.552 ;
     RECT  42.253 1.68 42.565 13.368 ;
     RECT  40.565 17.664 42.565 17.688 ;
     RECT  42.541 30.288 42.572 36.6 ;
     RECT  42.565 17.088 42.577 17.688 ;
     RECT  41.965 43.824 42.581 43.848 ;
     RECT  42.565 0.096 42.613 13.368 ;
     RECT  41.033 14.4 42.613 14.424 ;
     RECT  42.572 29.856 42.659 36.6 ;
     RECT  42.517 18.816 42.661 19.656 ;
     RECT  42.421 22.464 42.725 22.824 ;
     RECT  42.725 22.8 42.757 22.824 ;
     RECT  42.073 15.456 42.793 15.48 ;
     RECT  42.289 27.36 42.793 28.248 ;
     RECT  42.793 15.456 42.805 15.672 ;
     RECT  42.793 26.688 42.833 28.248 ;
     RECT  42.661 18.816 42.869 19.992 ;
     RECT  42.757 22.8 42.997 23.4 ;
     RECT  42.293 24.528 43.045 25.464 ;
     RECT  42.833 26.688 43.121 27.384 ;
     RECT  42.613 0.096 43.189 14.424 ;
     RECT  42.805 15.408 43.189 15.672 ;
     RECT  42.401 41.568 43.193 41.976 ;
     RECT  43.189 0.096 43.201 15.672 ;
     RECT  43.045 24.528 43.229 25.656 ;
     RECT  42.577 16.752 43.237 17.688 ;
     RECT  42.869 18.816 43.237 18.84 ;
     RECT  43.201 1.728 43.261 15.672 ;
     RECT  43.237 16.752 43.261 18.84 ;
     RECT  42.997 22.8 43.265 23.448 ;
     RECT  42.869 19.968 43.301 19.992 ;
     RECT  42.659 30.192 43.301 36.6 ;
     RECT  43.193 41.952 43.337 41.976 ;
     RECT  43.121 27.312 43.373 27.384 ;
     RECT  43.301 33.504 43.473 36.6 ;
     RECT  43.473 33.552 43.477 36.6 ;
     RECT  42.437 37.68 43.477 40.152 ;
     RECT  43.477 33.552 43.513 40.152 ;
     RECT  43.301 30.192 43.523 32.472 ;
     RECT  43.513 33.552 43.625 40.584 ;
     RECT  43.261 1.728 43.661 18.84 ;
     RECT  43.201 0.096 43.667 0.648 ;
     RECT  43.523 30.192 43.697 32.136 ;
     RECT  43.697 31.248 43.715 32.136 ;
     RECT  43.625 33.552 43.715 34.872 ;
     RECT  43.715 34.176 43.733 34.872 ;
     RECT  43.693 21.12 43.837 21.144 ;
     RECT  43.265 22.8 43.837 22.824 ;
     RECT  43.625 35.904 43.841 40.584 ;
     RECT  43.837 21.12 43.859 22.824 ;
     RECT  43.733 34.176 43.859 34.2 ;
     RECT  43.715 31.776 43.877 32.136 ;
     RECT  43.229 24.912 43.909 25.656 ;
     RECT  43.009 28.848 43.949 29.064 ;
     RECT  43.877 31.776 43.949 31.8 ;
     RECT  43.909 24.912 43.955 26.232 ;
     RECT  43.841 35.904 44.057 39.336 ;
     RECT  43.955 25.248 44.093 26.232 ;
     RECT  43.697 30.192 44.129 30.216 ;
     RECT  43.373 27.312 44.165 27.336 ;
     RECT  43.841 40.32 44.165 40.584 ;
     RECT  44.165 40.56 44.237 40.584 ;
     RECT  43.661 1.728 44.309 18.264 ;
     RECT  44.057 35.904 44.309 37.656 ;
     RECT  44.309 37.632 44.387 37.656 ;
     RECT  44.305 28.464 44.389 28.488 ;
     RECT  44.125 19.296 44.413 19.32 ;
     RECT  44.377 20.4 44.413 20.424 ;
     RECT  43.859 21.984 44.417 22.824 ;
     RECT  44.413 19.296 44.453 20.424 ;
     RECT  44.309 35.904 44.461 36.504 ;
     RECT  44.093 26.16 44.476 26.184 ;
     RECT  44.309 1.728 44.521 3.48 ;
     RECT  44.453 19.92 44.525 20.424 ;
     RECT  44.417 21.984 44.525 22.728 ;
     RECT  44.341 23.856 44.525 23.88 ;
     RECT  44.525 20.064 44.561 20.424 ;
     RECT  44.057 38.928 44.561 38.952 ;
     RECT  44.309 5.184 44.633 18.264 ;
     RECT  44.633 5.184 44.741 17.256 ;
     RECT  44.525 22.704 44.771 22.728 ;
     RECT  44.521 1.68 44.777 3.48 ;
     RECT  44.741 5.184 44.819 5.496 ;
     RECT  44.819 5.28 44.849 5.496 ;
     RECT  44.665 18.576 44.849 18.744 ;
     RECT  44.741 6.72 44.867 17.256 ;
     RECT  44.849 18.672 44.867 18.744 ;
     RECT  44.849 5.28 44.885 5.304 ;
     RECT  44.867 18.672 44.885 18.696 ;
     RECT  44.867 7.968 44.915 17.256 ;
     RECT  43.667 0.096 44.921 0.6 ;
     RECT  44.915 7.968 44.921 16.152 ;
     RECT  44.915 17.136 44.957 17.256 ;
     RECT  44.921 8.352 45.011 16.152 ;
     RECT  45.011 12 45.059 16.152 ;
     RECT  44.867 6.72 45.065 6.744 ;
     RECT  45.059 13.536 45.065 16.152 ;
     RECT  45.065 13.68 45.101 14.28 ;
     RECT  45.065 15.408 45.101 16.152 ;
     RECT  44.957 17.232 45.101 17.256 ;
     RECT  44.561 20.064 45.137 20.088 ;
     RECT  45.011 8.352 45.155 10.872 ;
     RECT  45.155 8.544 45.173 10.872 ;
     RECT  45.101 15.456 45.173 16.152 ;
     RECT  44.921 0.096 45.203 0.552 ;
     RECT  45.173 8.544 45.203 9.144 ;
     RECT  45.173 10.224 45.245 10.872 ;
     RECT  45.059 12 45.245 12.552 ;
     RECT  44.461 36.48 45.245 36.504 ;
     RECT  44.777 1.68 45.251 3.432 ;
     RECT  45.245 10.224 45.251 10.248 ;
     RECT  45.203 9.12 45.289 9.144 ;
     RECT  45.101 14.256 45.289 14.28 ;
     RECT  45.251 1.68 45.299 2.904 ;
     RECT  45.299 1.68 45.491 1.704 ;
     RECT  45.299 2.88 45.587 2.904 ;
     RECT  45.203 0.096 45.713 0.12 ;
    LAYER M5 ;
     RECT  42.192 0.016 45.672 0.131 ;
     RECT  0.72 0.016 12.936 1.907 ;
     RECT  7.056 1.907 12.936 2.137 ;
     RECT  7.056 2.137 13.32 2.151 ;
     RECT  18.6 2.137 18.72 2.151 ;
     RECT  24 2.137 24.12 2.151 ;
     RECT  29.4 2.137 29.52 2.151 ;
     RECT  34.8 2.137 34.92 2.151 ;
     RECT  40.2 2.137 40.32 2.151 ;
     RECT  7.056 2.151 13.512 2.243 ;
     RECT  7.152 2.243 13.512 2.291 ;
     RECT  24 2.151 24.312 2.485 ;
     RECT  40.2 2.151 40.512 2.533 ;
     RECT  18.6 2.151 18.912 2.629 ;
     RECT  20.16 2.677 20.184 2.725 ;
     RECT  29.4 2.151 29.712 2.821 ;
     RECT  12.048 2.291 13.512 2.867 ;
     RECT  20.16 2.725 20.568 2.869 ;
     RECT  42.192 0.131 45.576 2.869 ;
     RECT  0.72 1.907 6.024 2.915 ;
     RECT  42 2.869 45.576 2.915 ;
     RECT  0.816 2.915 6.024 3.301 ;
     RECT  7.152 2.291 10.776 3.301 ;
     RECT  19.968 2.869 20.568 3.349 ;
     RECT  28.656 2.821 29.712 3.349 ;
     RECT  40.2 2.533 40.728 3.635 ;
     RECT  34.8 2.151 35.112 3.685 ;
     RECT  24 2.485 24.552 3.875 ;
     RECT  12.72 2.867 13.512 3.925 ;
     RECT  14.544 2.245 14.712 3.925 ;
     RECT  16.032 3.589 16.056 3.925 ;
     RECT  40.2 3.635 40.632 3.925 ;
     RECT  18.384 2.629 18.912 4.357 ;
     RECT  19.968 3.349 20.616 4.451 ;
     RECT  42 2.915 45.24 4.451 ;
     RECT  12.72 3.925 14.712 4.501 ;
     RECT  16.032 3.925 16.296 4.501 ;
     RECT  17.616 4.357 18.912 4.501 ;
     RECT  40.08 3.925 40.632 4.501 ;
     RECT  43.296 4.451 45.24 4.595 ;
     RECT  33.648 2.245 33.672 4.691 ;
     RECT  0.816 3.301 10.776 4.741 ;
     RECT  19.968 4.451 20.568 4.931 ;
     RECT  34.8 3.685 35.928 5.077 ;
     RECT  32.112 5.077 32.136 5.125 ;
     RECT  17.328 4.501 18.912 5.267 ;
     RECT  39.6 4.501 40.632 5.411 ;
     RECT  28.656 3.349 30.264 5.459 ;
     RECT  34.464 5.077 35.928 5.557 ;
     RECT  34.464 5.557 36.168 5.603 ;
     RECT  12.72 4.501 16.296 5.795 ;
     RECT  0.816 4.741 11.256 5.797 ;
     RECT  12.72 5.795 16.2 5.797 ;
     RECT  28.656 5.459 29.712 5.893 ;
     RECT  24 3.875 24.312 5.989 ;
     RECT  23.472 5.989 24.312 6.229 ;
     RECT  26.016 6.133 26.04 6.229 ;
     RECT  32.112 5.125 32.472 6.275 ;
     RECT  23.472 6.229 26.04 6.277 ;
     RECT  0.816 5.797 16.2 6.323 ;
     RECT  0.816 6.323 14.664 6.419 ;
     RECT  42 4.451 42.024 6.421 ;
     RECT  17.616 5.267 18.912 6.515 ;
     RECT  34.464 5.603 35.112 6.611 ;
     RECT  34.56 6.611 35.112 6.661 ;
     RECT  36.144 5.603 36.168 6.661 ;
     RECT  19.968 4.931 19.992 6.707 ;
     RECT  27.504 6.661 27.528 6.709 ;
     RECT  28.512 5.893 29.712 6.709 ;
     RECT  34.56 6.661 36.168 6.709 ;
     RECT  34.56 6.709 36.84 6.805 ;
     RECT  38.496 5.605 38.52 6.805 ;
     RECT  39.6 5.411 40.512 6.805 ;
     RECT  18.48 6.515 18.912 6.851 ;
     RECT  23.28 6.277 26.04 6.851 ;
     RECT  0.816 6.419 0.936 6.899 ;
     RECT  32.448 6.275 32.472 6.899 ;
     RECT  1.968 6.419 14.664 6.947 ;
     RECT  16.08 6.323 16.2 7.043 ;
     RECT  27.504 6.709 29.712 7.189 ;
     RECT  27.456 7.189 30.696 7.333 ;
     RECT  2.256 6.947 14.664 7.381 ;
     RECT  16.08 7.043 16.104 7.381 ;
     RECT  27.456 7.333 31.272 7.381 ;
     RECT  42 6.421 42.552 7.429 ;
     RECT  43.536 4.595 45.24 7.429 ;
     RECT  34.56 6.805 40.632 7.667 ;
     RECT  37.344 7.667 40.632 8.051 ;
     RECT  34.56 7.667 36.168 8.099 ;
     RECT  34.8 8.099 36.168 8.435 ;
     RECT  21.072 8.389 21.096 8.437 ;
     RECT  37.344 8.051 40.512 8.531 ;
     RECT  0.816 6.899 0.84 8.579 ;
     RECT  2.256 7.381 16.104 8.579 ;
     RECT  2.256 8.579 15.384 8.675 ;
     RECT  38.16 8.531 40.512 8.723 ;
     RECT  2.4 8.675 15.384 9.011 ;
     RECT  27.312 7.381 31.272 9.013 ;
     RECT  15.36 9.011 15.384 9.155 ;
     RECT  42 7.429 45.24 9.155 ;
     RECT  2.4 9.011 14.232 9.443 ;
     RECT  39.408 8.723 40.512 9.589 ;
     RECT  39.408 9.589 41.016 9.877 ;
     RECT  42 9.155 45.192 9.877 ;
     RECT  39.408 9.877 45.192 9.923 ;
     RECT  38.16 8.723 38.184 10.165 ;
     RECT  39.408 9.923 40.512 10.165 ;
     RECT  41.664 9.923 45.192 10.213 ;
     RECT  2.4 9.443 10.44 10.307 ;
     RECT  34.8 8.435 35.832 10.309 ;
     RECT  20.784 8.437 21.096 10.355 ;
     RECT  23.472 6.851 26.04 10.453 ;
     RECT  27.312 9.013 31.32 10.453 ;
     RECT  38.16 10.165 40.512 10.501 ;
     RECT  17.472 10.213 17.496 10.883 ;
     RECT  41.664 10.213 45.24 10.883 ;
     RECT  34.8 10.309 36.12 10.933 ;
     RECT  34.608 10.933 36.12 11.173 ;
     RECT  38.112 10.501 40.512 11.173 ;
     RECT  11.424 9.443 14.232 11.267 ;
     RECT  21.072 10.355 21.096 11.317 ;
     RECT  34.032 11.173 36.12 11.365 ;
     RECT  20.448 11.317 21.096 11.459 ;
     RECT  23.472 10.453 31.32 11.459 ;
     RECT  33.408 11.365 36.12 11.459 ;
     RECT  26.016 11.459 30.984 11.555 ;
     RECT  2.4 10.307 10.296 11.747 ;
     RECT  42.048 10.883 45.24 11.941 ;
     RECT  11.424 11.267 14.088 12.035 ;
     RECT  33.408 11.459 36.072 12.083 ;
     RECT  15.504 10.933 15.528 12.131 ;
     RECT  37.44 11.173 40.512 12.325 ;
     RECT  27.072 11.555 30.984 12.371 ;
     RECT  21.648 12.181 21.672 12.469 ;
     RECT  11.472 12.035 14.088 12.611 ;
     RECT  26.016 11.555 26.04 12.853 ;
     RECT  37.296 12.325 40.512 12.899 ;
     RECT  32.4 12.853 32.424 13.045 ;
     RECT  33.408 12.083 33.432 13.045 ;
     RECT  34.608 12.083 36.072 13.045 ;
     RECT  27.072 12.371 30.696 13.331 ;
     RECT  32.256 13.045 33.432 13.333 ;
     RECT  34.608 13.045 36.264 13.333 ;
     RECT  32.256 13.333 36.264 13.381 ;
     RECT  37.296 12.899 37.32 13.381 ;
     RECT  27.504 13.331 30.696 13.571 ;
     RECT  32.256 13.381 37.32 13.573 ;
     RECT  21.648 12.469 21.768 13.715 ;
     RECT  31.776 13.573 37.32 13.715 ;
     RECT  26.016 12.853 26.088 13.909 ;
     RECT  2.4 11.747 9.624 14.243 ;
     RECT  27.504 13.571 30.648 14.291 ;
     RECT  41.568 11.941 45.24 14.291 ;
     RECT  27.6 14.291 30.648 14.339 ;
     RECT  16.656 13.429 16.68 14.387 ;
     RECT  12.048 12.611 14.088 14.629 ;
     RECT  18.6 6.851 18.912 14.629 ;
     RECT  12.048 14.629 14.376 14.771 ;
     RECT  31.776 13.715 33.432 14.771 ;
     RECT  31.776 14.771 33.336 14.819 ;
     RECT  23.472 11.459 24.312 14.867 ;
     RECT  25.632 13.909 26.088 14.963 ;
     RECT  23.904 14.867 24.312 15.061 ;
     RECT  20.448 11.459 20.472 15.349 ;
     RECT  21.648 13.715 21.672 15.349 ;
     RECT  20.448 15.349 21.672 15.589 ;
     RECT  41.568 14.291 45.048 15.589 ;
     RECT  10.656 14.629 10.68 15.683 ;
     RECT  12.624 14.771 14.376 15.827 ;
     RECT  32.112 14.819 33.336 15.829 ;
     RECT  38.592 12.899 40.512 15.829 ;
     RECT  41.568 15.589 45.096 15.829 ;
     RECT  27.696 14.339 30.552 15.971 ;
     RECT  23.904 15.061 24.504 16.019 ;
     RECT  25.632 14.963 25.656 16.019 ;
     RECT  27.696 15.971 27.72 16.019 ;
     RECT  28.752 15.971 30.552 16.019 ;
     RECT  34.608 13.715 37.32 16.019 ;
     RECT  38.592 15.829 45.096 16.019 ;
     RECT  38.592 16.019 39.192 16.259 ;
     RECT  31.584 15.829 33.336 16.355 ;
     RECT  36.912 16.019 37.32 16.499 ;
     RECT  38.592 16.259 38.904 16.501 ;
     RECT  9.168 14.243 9.624 16.595 ;
     RECT  29.088 16.019 29.712 16.691 ;
     RECT  2.4 14.243 8.112 16.693 ;
     RECT  9.168 16.595 9.24 16.693 ;
     RECT  20.448 15.589 22.2 16.835 ;
     RECT  32.112 16.355 33.336 16.835 ;
     RECT  2.4 16.693 9.24 17.123 ;
     RECT  32.256 16.835 33.336 17.123 ;
     RECT  20.448 16.835 20.472 17.171 ;
     RECT  9.168 17.123 9.24 17.267 ;
     RECT  36.912 16.499 36.936 17.603 ;
     RECT  22.176 16.835 22.2 17.699 ;
     RECT  40.2 16.019 45.096 17.699 ;
     RECT  34.608 16.019 35.832 18.419 ;
     RECT  37.968 16.501 38.904 18.419 ;
     RECT  32.256 17.123 32.28 18.421 ;
     RECT  36.528 18.853 36.552 19.043 ;
     RECT  38.592 18.419 38.904 19.093 ;
     RECT  31.872 18.421 32.28 19.333 ;
     RECT  33.312 17.123 33.336 19.333 ;
     RECT  12.768 15.827 14.376 19.427 ;
     RECT  31.872 19.333 33.336 19.427 ;
     RECT  32.256 19.427 33.336 19.811 ;
     RECT  29.4 16.691 29.712 19.861 ;
     RECT  12.768 19.427 13.944 20.533 ;
     RECT  9.168 17.267 9.192 20.675 ;
     RECT  24 16.019 24.312 20.725 ;
     RECT  2.4 17.123 8.112 21.107 ;
     RECT  32.256 19.811 32.28 21.395 ;
     RECT  23.472 20.725 24.312 21.539 ;
     RECT  12.672 20.533 13.944 21.683 ;
     RECT  3.696 21.107 8.112 21.731 ;
     RECT  36.912 20.389 36.936 22.021 ;
     RECT  38.592 19.093 39.096 22.021 ;
     RECT  13.2 21.683 13.944 22.211 ;
     RECT  7.584 21.731 8.112 22.259 ;
     RECT  21.408 22.165 21.432 22.261 ;
     RECT  3.696 21.731 6.552 22.499 ;
     RECT  17.76 14.629 18.912 22.547 ;
     RECT  21.408 22.261 21.48 22.597 ;
     RECT  18.6 22.547 18.912 22.741 ;
     RECT  40.2 17.699 40.512 22.741 ;
     RECT  42.432 17.699 45.096 22.835 ;
     RECT  15.696 22.693 15.72 23.029 ;
     RECT  15.696 23.029 16.008 23.125 ;
     RECT  36.912 22.021 39.096 23.269 ;
     RECT  3.888 22.499 6.552 23.411 ;
     RECT  36.576 23.269 39.096 23.411 ;
     RECT  43.008 22.835 43.416 23.459 ;
     RECT  15.696 23.125 16.728 23.555 ;
     RECT  29.4 19.861 29.928 23.653 ;
     RECT  34.608 18.419 35.544 23.699 ;
     RECT  18.6 22.741 19.368 23.795 ;
     RECT  29.184 23.653 29.928 23.843 ;
     RECT  15.984 23.555 16.728 23.987 ;
     RECT  20.736 22.597 21.48 24.181 ;
     RECT  22.608 24.133 22.632 24.181 ;
     RECT  20.736 24.181 22.632 24.371 ;
     RECT  37.872 23.411 39.096 24.469 ;
     RECT  40.2 22.741 40.92 24.469 ;
     RECT  43.104 23.459 43.416 24.469 ;
     RECT  16.656 23.987 16.728 24.563 ;
     RECT  21.456 24.371 22.632 24.563 ;
     RECT  36.576 23.411 36.6 24.707 ;
     RECT  24 21.539 24.312 24.757 ;
     RECT  4.848 23.411 6.552 24.899 ;
     RECT  42.192 24.469 43.416 24.901 ;
     RECT  5.808 24.899 6.552 25.045 ;
     RECT  7.68 22.259 8.112 25.045 ;
     RECT  13.2 22.211 13.848 25.045 ;
     RECT  5.808 25.045 8.112 25.139 ;
     RECT  37.872 24.469 40.92 25.139 ;
     RECT  42.192 24.901 43.944 25.139 ;
     RECT  5.808 25.139 5.832 25.475 ;
     RECT  42.192 25.139 42.216 25.475 ;
     RECT  6.912 25.139 8.112 25.715 ;
     RECT  33.312 19.811 33.336 25.813 ;
     RECT  34.608 23.699 35.112 25.813 ;
     RECT  12.576 25.045 13.848 25.955 ;
     RECT  43.92 25.139 43.944 26.149 ;
     RECT  45.072 22.835 45.096 26.149 ;
     RECT  39.072 25.139 40.92 26.243 ;
     RECT  43.92 26.149 45.096 26.243 ;
     RECT  13.2 25.955 13.848 26.245 ;
     RECT  16.656 24.563 16.68 26.291 ;
     RECT  21.648 24.563 22.632 26.291 ;
     RECT  29.4 23.843 29.928 26.531 ;
     RECT  29.4 26.531 29.712 26.677 ;
     RECT  39.072 26.243 39.096 26.819 ;
     RECT  21.696 26.291 22.632 26.867 ;
     RECT  18.6 23.795 18.912 27.205 ;
     RECT  33.312 25.813 35.112 27.395 ;
     RECT  40.2 26.243 40.92 27.395 ;
     RECT  7.44 25.715 8.112 27.877 ;
     RECT  42.816 26.725 42.84 27.877 ;
     RECT  23.76 24.757 24.312 27.923 ;
     RECT  17.664 27.205 18.912 27.971 ;
     RECT  21.696 26.867 22.536 28.213 ;
     RECT  44.4 26.243 45.096 28.453 ;
     RECT  33.744 27.395 35.112 28.501 ;
     RECT  21.312 28.213 22.536 28.691 ;
     RECT  42.192 27.877 42.84 28.837 ;
     RECT  44.352 28.453 45.096 28.837 ;
     RECT  20.16 27.205 20.184 28.931 ;
     RECT  33.744 28.501 35.592 29.123 ;
     RECT  31.68 26.581 31.704 29.365 ;
     RECT  32.688 28.453 32.712 29.365 ;
     RECT  21.312 28.691 21.336 29.699 ;
     RECT  31.68 29.365 32.712 30.035 ;
     RECT  31.68 30.035 32.568 30.275 ;
     RECT  24 27.923 24.312 30.373 ;
     RECT  22.512 28.691 22.536 30.611 ;
     RECT  29.232 26.677 29.712 30.661 ;
     RECT  37.872 25.139 37.896 30.709 ;
     RECT  29.136 30.661 29.712 31.091 ;
     RECT  24 30.373 24.408 31.141 ;
     RECT  13.2 26.245 13.944 31.285 ;
     RECT  42.192 28.837 45.096 31.285 ;
     RECT  11.232 25.285 11.256 31.379 ;
     RECT  30.768 30.949 30.792 31.379 ;
     RECT  37.872 30.709 38.712 31.427 ;
     RECT  32.544 30.275 32.568 31.475 ;
     RECT  12.912 31.285 13.944 31.525 ;
     RECT  40.2 27.395 40.512 32.101 ;
     RECT  41.904 31.285 45.096 32.101 ;
     RECT  18.6 27.971 18.912 32.245 ;
     RECT  24 31.141 25.128 32.531 ;
     RECT  18.6 32.245 19.368 32.965 ;
     RECT  17.616 32.965 19.368 33.205 ;
     RECT  12.048 31.525 13.944 33.299 ;
     RECT  17.328 33.205 19.368 33.395 ;
     RECT  21.936 31.285 22.44 33.445 ;
     RECT  24 32.531 24.312 33.445 ;
     RECT  17.568 33.395 19.368 33.635 ;
     RECT  20.688 30.661 20.712 33.781 ;
     RECT  26.208 31.765 26.232 33.827 ;
     RECT  36.816 30.181 36.84 34.069 ;
     RECT  7.344 27.877 8.112 34.741 ;
     RECT  32.496 33.013 32.52 34.787 ;
     RECT  33.744 29.123 35.112 34.789 ;
     RECT  36.288 34.069 36.84 34.789 ;
     RECT  21.936 33.445 24.312 34.981 ;
     RECT  17.568 33.635 18.912 35.123 ;
     RECT  29.232 31.091 29.712 35.269 ;
     RECT  7.344 34.741 8.664 35.363 ;
     RECT  12.048 33.299 13.608 35.363 ;
     RECT  21.936 34.981 24.408 35.363 ;
     RECT  27.312 33.589 27.336 35.557 ;
     RECT  17.616 35.123 18.912 35.605 ;
     RECT  20.064 33.781 20.712 35.605 ;
     RECT  40.2 32.101 45.096 35.699 ;
     RECT  33.744 34.789 36.84 35.891 ;
     RECT  15.936 31.861 15.96 35.893 ;
     RECT  14.688 34.501 14.712 36.085 ;
     RECT  15.936 35.893 16.632 36.085 ;
     RECT  17.616 35.605 20.712 36.275 ;
     RECT  33.888 35.891 36.84 36.275 ;
     RECT  26.4 35.557 27.336 36.419 ;
     RECT  26.736 36.419 27.336 36.515 ;
     RECT  42.72 35.699 45.096 36.515 ;
     RECT  42.72 36.515 44.376 36.611 ;
     RECT  22.176 35.363 24.408 36.661 ;
     RECT  9.648 32.197 9.672 36.997 ;
     RECT  7.344 35.363 8.616 37.091 ;
     RECT  33.888 36.275 36.456 37.573 ;
     RECT  43.68 36.611 44.376 37.667 ;
     RECT  12.048 35.363 12.072 37.909 ;
     RECT  13.2 35.363 13.608 37.909 ;
     RECT  5.04 31.381 5.064 38.053 ;
     RECT  5.04 38.053 5.976 38.101 ;
     RECT  17.616 36.275 20.52 38.149 ;
     RECT  28.464 35.269 29.712 38.675 ;
     RECT  12.048 37.909 13.608 38.725 ;
     RECT  14.688 36.085 16.632 38.725 ;
     RECT  12.048 38.725 16.632 38.819 ;
     RECT  22.176 36.661 24.888 38.819 ;
     RECT  43.68 37.667 43.848 38.819 ;
     RECT  40.2 35.699 41.736 39.059 ;
     RECT  26.736 36.515 26.76 39.061 ;
     RECT  26.64 39.061 26.76 39.107 ;
     RECT  33.888 37.573 36.504 39.107 ;
     RECT  43.68 38.819 43.704 39.251 ;
     RECT  40.2 39.059 41.352 39.253 ;
     RECT  5.04 38.101 6.216 39.395 ;
     RECT  9.648 36.997 9.72 39.395 ;
     RECT  26.64 39.107 26.664 39.395 ;
     RECT  16.608 38.819 16.632 39.443 ;
     RECT  37.872 31.427 37.896 39.637 ;
     RECT  17.616 38.149 21.144 39.731 ;
     RECT  29.4 38.675 29.712 39.877 ;
     RECT  12.048 38.819 15.384 39.923 ;
     RECT  22.416 38.819 24.888 39.923 ;
     RECT  34.608 39.107 36.504 40.403 ;
     RECT  22.416 39.923 24.408 40.405 ;
     RECT  37.872 39.637 38.808 40.405 ;
     RECT  39.888 39.253 41.352 40.405 ;
     RECT  18.6 39.731 21.144 40.451 ;
     RECT  13.2 39.923 15.384 40.499 ;
     RECT  29.28 39.877 29.712 40.549 ;
     RECT  12.048 39.923 12.072 40.595 ;
     RECT  7.344 37.091 8.112 40.645 ;
     RECT  9.648 39.395 9.672 40.645 ;
     RECT  29.184 40.549 29.712 40.691 ;
     RECT  36.528 40.405 36.552 41.219 ;
     RECT  22.176 40.405 24.408 41.411 ;
     RECT  7.344 40.645 9.672 41.651 ;
     RECT  22.176 41.411 24.312 41.651 ;
     RECT  37.872 40.405 41.352 41.699 ;
     RECT  37.872 41.699 41.016 41.747 ;
     RECT  2.4 21.107 2.712 42.133 ;
     RECT  13.2 40.499 14.856 42.133 ;
     RECT  18.6 40.451 20.904 42.133 ;
     RECT  13.2 42.133 15.144 42.179 ;
     RECT  37.872 41.747 40.824 42.275 ;
     RECT  13.2 42.179 14.136 42.467 ;
     RECT  5.04 39.395 5.064 42.803 ;
     RECT  18.6 42.133 21.096 42.803 ;
     RECT  2.4 42.133 3.288 42.851 ;
     RECT  6.24 41.653 6.264 42.851 ;
     RECT  30.816 42.757 30.84 43.043 ;
     RECT  34.608 40.403 35.112 43.043 ;
     RECT  15.12 42.179 15.144 43.283 ;
     RECT  22.32 41.651 24.312 43.379 ;
     RECT  19.968 42.803 21.096 43.571 ;
     RECT  22.32 43.379 22.824 43.571 ;
     RECT  39.456 42.275 40.824 43.811 ;
     RECT  19.968 43.571 20.328 44.051 ;
     RECT  20.304 44.051 20.328 44.099 ;
     RECT  40.2 43.811 40.824 44.099 ;
     RECT  22.32 43.571 22.344 44.147 ;
     RECT  7.8 41.651 9.672 44.195 ;
     RECT  9.648 44.195 9.672 44.435 ;
     RECT  29.28 40.691 29.712 44.483 ;
     RECT  38.928 44.053 38.952 44.915 ;
     RECT  37.872 42.275 37.896 45.013 ;
     RECT  2.4 42.851 2.712 45.369 ;
     RECT  7.8 44.195 8.112 45.369 ;
     RECT  13.2 42.467 13.512 45.369 ;
     RECT  18.6 42.803 18.912 45.369 ;
     RECT  24 43.379 24.312 45.369 ;
     RECT  29.4 44.483 29.712 45.369 ;
     RECT  34.8 43.043 35.112 45.369 ;
     RECT  40.2 44.099 40.512 45.369 ;
     RECT  2.4 45.369 2.52 45.383 ;
     RECT  7.8 45.369 7.92 45.383 ;
     RECT  13.2 45.369 13.32 45.383 ;
     RECT  18.6 45.369 18.72 45.383 ;
     RECT  24 45.369 24.12 45.383 ;
     RECT  29.4 45.369 29.52 45.383 ;
     RECT  34.8 45.369 34.92 45.383 ;
     RECT  40.2 45.369 40.32 45.383 ;
     RECT  37.872 45.013 38.088 47.504 ;
     RECT  6.024 1.907 7.056 2.243 ;
     RECT  6.024 2.243 7.152 3.301 ;
     RECT  13.512 2.245 14.544 3.925 ;
     RECT  33.672 2.245 34.8 4.691 ;
     RECT  10.776 2.291 12.048 2.867 ;
     RECT  40.728 2.533 42.192 2.869 ;
     RECT  18.912 2.677 20.16 2.869 ;
     RECT  18.912 2.869 19.968 6.707 ;
     RECT  40.728 2.869 42 3.635 ;
     RECT  14.712 3.589 16.032 4.501 ;
     RECT  40.632 3.635 42 5.411 ;
     RECT  16.296 4.357 17.616 4.501 ;
     RECT  42.024 4.451 43.296 4.595 ;
     RECT  16.296 4.501 17.328 5.267 ;
     RECT  42.024 4.595 43.536 6.421 ;
     RECT  34.464 4.691 34.8 5.077 ;
     RECT  11.256 4.741 12.72 5.797 ;
     RECT  16.296 5.267 17.616 5.795 ;
     RECT  40.512 5.411 42 6.805 ;
     RECT  35.112 5.603 36.144 6.661 ;
     RECT  38.52 5.605 39.6 6.805 ;
     RECT  16.2 5.795 17.616 6.515 ;
     RECT  14.664 6.323 16.08 7.381 ;
     RECT  0.936 6.419 1.968 6.899 ;
     RECT  42.552 6.421 43.536 7.429 ;
     RECT  26.04 6.661 27.504 7.189 ;
     RECT  27.528 6.661 28.512 6.709 ;
     RECT  40.632 6.805 42 8.051 ;
     RECT  0.84 6.899 1.968 6.947 ;
     RECT  0.84 6.947 2.256 8.579 ;
     RECT  26.04 7.189 27.456 7.381 ;
     RECT  26.04 7.381 27.312 10.453 ;
     RECT  36.168 7.667 37.344 8.435 ;
     RECT  40.512 8.051 42 9.589 ;
     RECT  35.832 8.435 37.344 8.531 ;
     RECT  38.184 8.723 39.408 10.165 ;
     RECT  14.232 9.011 15.36 9.155 ;
     RECT  45.192 9.155 45.24 10.213 ;
     RECT  10.44 9.443 11.424 10.307 ;
     RECT  41.016 9.589 42 9.877 ;
     RECT  40.512 9.923 41.664 10.883 ;
     RECT  17.496 10.213 18.6 10.883 ;
     RECT  10.296 10.307 11.424 11.747 ;
     RECT  20.784 10.355 21.072 11.317 ;
     RECT  40.512 10.883 42.048 11.941 ;
     RECT  14.232 10.933 15.504 11.267 ;
     RECT  36.12 11.173 37.44 11.459 ;
     RECT  14.088 11.267 15.504 12.131 ;
     RECT  20.472 11.459 21.096 12.181 ;
     RECT  30.984 11.459 31.32 12.371 ;
     RECT  36.072 11.459 37.44 12.325 ;
     RECT  26.04 11.555 27.072 12.853 ;
     RECT  40.512 11.941 41.568 15.829 ;
     RECT  33.432 12.083 34.608 13.333 ;
     RECT  20.472 12.181 21.648 15.349 ;
     RECT  36.072 12.325 37.296 13.045 ;
     RECT  30.696 12.371 31.32 12.853 ;
     RECT  26.088 12.853 27.072 13.331 ;
     RECT  30.696 12.853 32.4 13.045 ;
     RECT  32.424 12.853 33.408 13.045 ;
     RECT  37.32 12.899 38.592 16.499 ;
     RECT  30.696 13.045 32.256 13.571 ;
     RECT  36.264 13.045 37.296 13.381 ;
     RECT  26.088 13.331 27.504 14.291 ;
     RECT  30.648 13.571 32.256 13.573 ;
     RECT  30.648 13.573 31.776 14.339 ;
     RECT  33.432 13.715 34.608 14.771 ;
     RECT  24.312 13.909 25.632 15.061 ;
     RECT  8.112 14.243 9.168 16.693 ;
     RECT  26.088 14.291 27.6 14.339 ;
     RECT  45.048 14.291 45.096 15.589 ;
     RECT  30.552 14.339 31.776 14.819 ;
     RECT  9.624 14.629 10.656 15.683 ;
     RECT  10.68 14.629 12.048 14.771 ;
     RECT  33.336 14.771 34.608 25.813 ;
     RECT  30.552 14.819 32.112 15.829 ;
     RECT  24.504 15.061 25.632 16.019 ;
     RECT  30.552 15.829 31.584 16.019 ;
     RECT  27.72 15.971 28.752 16.019 ;
     RECT  35.832 16.019 36.912 17.603 ;
     RECT  39.192 16.019 40.2 16.259 ;
     RECT  38.904 16.259 40.2 19.093 ;
     RECT  36.936 16.499 38.592 16.501 ;
     RECT  36.936 16.501 37.968 17.603 ;
     RECT  8.112 17.123 9.168 20.675 ;
     RECT  32.28 17.123 33.312 19.333 ;
     RECT  35.832 17.603 37.968 18.419 ;
     RECT  35.544 18.419 36.552 18.853 ;
     RECT  35.544 18.853 36.528 19.043 ;
     RECT  35.544 19.043 36.552 20.389 ;
     RECT  39.096 19.093 40.2 24.469 ;
     RECT  32.28 19.811 33.312 21.395 ;
     RECT  35.544 20.389 36.912 23.269 ;
     RECT  2.712 21.107 3.696 22.499 ;
     RECT  6.552 21.731 7.584 22.259 ;
     RECT  6.552 22.259 7.68 25.045 ;
     RECT  2.712 22.499 3.888 23.411 ;
     RECT  19.368 22.741 20.736 23.795 ;
     RECT  40.92 22.741 42.432 22.835 ;
     RECT  35.544 23.269 36.576 23.699 ;
     RECT  36.6 23.411 37.872 24.707 ;
     RECT  43.008 23.459 43.104 24.469 ;
     RECT  35.112 23.699 36.576 24.707 ;
     RECT  21.48 24.133 22.608 24.181 ;
     RECT  22.632 24.133 24 24.757 ;
     RECT  40.92 24.469 42.192 25.475 ;
     RECT  22.632 24.757 23.76 26.867 ;
     RECT  43.944 24.901 45.072 26.149 ;
     RECT  5.832 25.139 6.912 25.475 ;
     RECT  37.896 25.139 39.072 26.819 ;
     RECT  11.256 25.285 12.576 25.955 ;
     RECT  39.096 26.243 40.2 26.819 ;
     RECT  21.648 26.291 21.696 27.205 ;
     RECT  22.536 26.867 23.76 27.923 ;
     RECT  18.912 27.205 20.16 28.931 ;
     RECT  20.184 27.205 21.696 28.213 ;
     RECT  33.312 27.395 33.744 28.453 ;
     RECT  22.536 27.923 24 30.611 ;
     RECT  20.184 28.213 21.312 28.931 ;
     RECT  31.704 28.453 32.688 29.365 ;
     RECT  32.712 28.453 33.744 30.035 ;
     RECT  42.84 28.453 44.352 28.837 ;
     RECT  21.336 28.691 22.512 29.699 ;
     RECT  32.568 30.035 33.744 31.475 ;
     RECT  36.84 30.181 37.872 36.275 ;
     RECT  38.712 30.709 40.2 31.427 ;
     RECT  29.712 30.949 30.768 31.379 ;
     RECT  20.712 31.285 21.936 35.363 ;
     RECT  40.512 31.285 41.904 32.101 ;
     RECT  25.128 31.765 26.208 32.531 ;
     RECT  19.368 32.245 20.688 33.635 ;
     RECT  32.52 33.013 33.744 34.787 ;
     RECT  15.96 33.205 17.328 33.395 ;
     RECT  13.608 33.299 13.944 34.501 ;
     RECT  26.232 33.589 27.312 33.827 ;
     RECT  18.912 33.635 20.688 33.781 ;
     RECT  18.912 33.781 20.064 35.605 ;
     RECT  35.112 34.069 36.288 34.789 ;
     RECT  13.608 34.501 14.688 38.725 ;
     RECT  14.712 34.501 15.936 36.085 ;
     RECT  8.664 34.741 9.648 35.363 ;
     RECT  17.568 35.123 17.616 35.893 ;
     RECT  27.336 35.269 28.464 36.515 ;
     RECT  8.616 35.363 9.648 37.091 ;
     RECT  12.072 35.363 13.2 37.909 ;
     RECT  20.712 35.363 22.176 36.275 ;
     RECT  41.736 35.699 42.72 36.611 ;
     RECT  16.632 35.893 17.616 39.443 ;
     RECT  36.456 36.275 37.872 37.573 ;
     RECT  36.504 37.573 37.872 40.403 ;
     RECT  5.976 38.053 7.344 38.101 ;
     RECT  6.216 38.101 7.344 39.395 ;
     RECT  21.144 38.149 22.176 38.819 ;
     RECT  29.28 38.675 29.4 39.877 ;
     RECT  15.384 38.819 16.608 39.443 ;
     RECT  21.144 38.819 22.416 40.405 ;
     RECT  38.808 39.637 39.888 40.405 ;
     RECT  12.072 39.923 13.2 40.595 ;
     RECT  35.112 40.403 37.872 40.405 ;
     RECT  21.144 40.405 22.176 40.451 ;
     RECT  35.112 40.405 36.528 41.219 ;
     RECT  36.552 40.405 37.872 41.219 ;
     RECT  20.904 40.451 22.176 41.651 ;
     RECT  20.904 41.651 22.32 42.133 ;
     RECT  5.064 41.653 6.24 42.803 ;
     RECT  21.096 42.133 22.32 43.571 ;
     RECT  14.136 42.179 15.12 42.467 ;
     RECT  29.712 42.757 30.816 43.043 ;
     RECT  18.912 42.803 19.968 44.051 ;
     RECT  22.824 43.379 24 43.571 ;
     RECT  39.456 43.811 40.2 44.053 ;
     RECT  18.912 44.051 20.304 44.099 ;
     RECT  37.896 44.053 38.928 44.915 ;
     RECT  38.952 44.053 40.2 44.915 ;
     RECT  37.896 44.915 38.088 45.013 ;
  END
END dsfd_coll_cesl
END LIBRARY
